VERSION 5.8 ;
BUSBITCHARS "[]" ;
DIVIDERCHAR "/" ;
UNITS
    DATABASE MICRONS 1000 ;
END UNITS

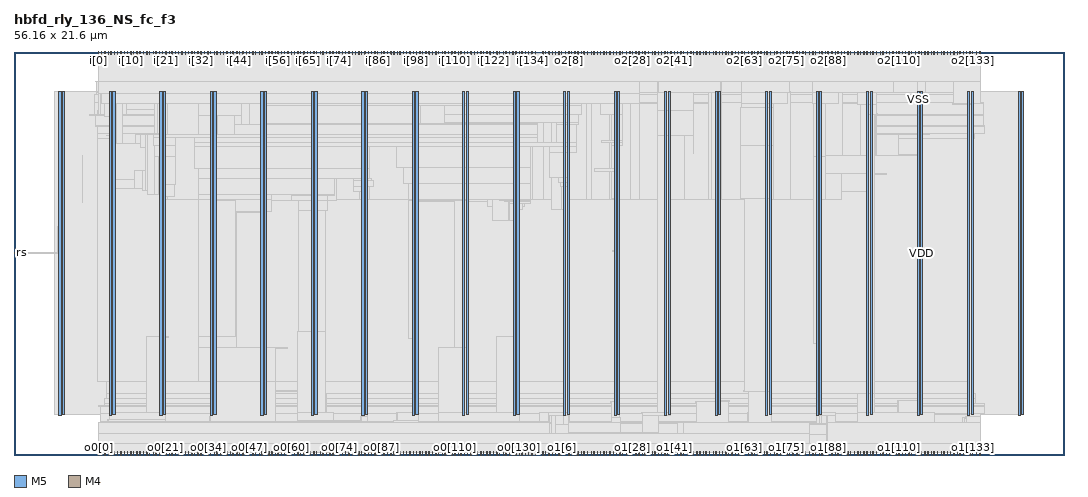
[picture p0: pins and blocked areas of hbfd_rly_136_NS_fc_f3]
MACRO hbfd_rly_136_NS_fc_f3
  FOREIGN hbfd_rly_136_NS_fc_f3 0 0 ;
  CLASS BLOCK ;
  SIZE 56.16 BY 21.6 ;
  PIN clk_in
    DIRECTION INPUT ;
    USE SIGNAL ;
    PORT
      LAYER M5 ;
        RECT  16.176 21.408 16.2 21.6 ;
    END
  END clk_in
  PIN clk_out0
    DIRECTION OUTPUT ;
    USE SIGNAL ;
    PORT
      LAYER M5 ;
        RECT  16.176 0 16.2 0.192 ;
    END
  END clk_out0
  PIN clk_out1
    DIRECTION OUTPUT ;
    USE SIGNAL ;
    PORT
      LAYER M5 ;
        RECT  39.936 0 39.96 0.192 ;
    END
  END clk_out1
  PIN clk_out2
    DIRECTION OUTPUT ;
    USE SIGNAL ;
    PORT
      LAYER M5 ;
        RECT  39.936 21.408 39.96 21.6 ;
    END
  END clk_out2
  PIN i[0]
    DIRECTION INPUT ;
    USE SIGNAL ;
    PORT
      LAYER M5 ;
        RECT  4.512 21.408 4.536 21.6 ;
    END
  END i[0]
  PIN i[100]
    DIRECTION INPUT ;
    USE SIGNAL ;
    PORT
      LAYER M5 ;
        RECT  21.84 21.408 21.864 21.6 ;
    END
  END i[100]
  PIN i[101]
    DIRECTION INPUT ;
    USE SIGNAL ;
    PORT
      LAYER M5 ;
        RECT  22.032 21.408 22.056 21.6 ;
    END
  END i[101]
  PIN i[102]
    DIRECTION INPUT ;
    USE SIGNAL ;
    PORT
      LAYER M5 ;
        RECT  22.176 21.408 22.2 21.6 ;
    END
  END i[102]
  PIN i[103]
    DIRECTION INPUT ;
    USE SIGNAL ;
    PORT
      LAYER M5 ;
        RECT  22.368 21.408 22.392 21.6 ;
    END
  END i[103]
  PIN i[104]
    DIRECTION INPUT ;
    USE SIGNAL ;
    PORT
      LAYER M5 ;
        RECT  22.56 21.408 22.584 21.6 ;
    END
  END i[104]
  PIN i[105]
    DIRECTION INPUT ;
    USE SIGNAL ;
    PORT
      LAYER M5 ;
        RECT  22.704 21.408 22.728 21.6 ;
    END
  END i[105]
  PIN i[106]
    DIRECTION INPUT ;
    USE SIGNAL ;
    PORT
      LAYER M5 ;
        RECT  22.896 21.408 22.92 21.6 ;
    END
  END i[106]
  PIN i[107]
    DIRECTION INPUT ;
    USE SIGNAL ;
    PORT
      LAYER M5 ;
        RECT  23.04 21.408 23.064 21.6 ;
    END
  END i[107]
  PIN i[108]
    DIRECTION INPUT ;
    USE SIGNAL ;
    PORT
      LAYER M5 ;
        RECT  23.232 21.408 23.256 21.6 ;
    END
  END i[108]
  PIN i[109]
    DIRECTION INPUT ;
    USE SIGNAL ;
    PORT
      LAYER M5 ;
        RECT  23.424 21.408 23.448 21.6 ;
    END
  END i[109]
  PIN i[10]
    DIRECTION INPUT ;
    USE SIGNAL ;
    PORT
      LAYER M5 ;
        RECT  6.24 21.408 6.264 21.6 ;
    END
  END i[10]
  PIN i[110]
    DIRECTION INPUT ;
    USE SIGNAL ;
    PORT
      LAYER M5 ;
        RECT  23.568 21.408 23.592 21.6 ;
    END
  END i[110]
  PIN i[111]
    DIRECTION INPUT ;
    USE SIGNAL ;
    PORT
      LAYER M5 ;
        RECT  23.76 21.408 23.784 21.6 ;
    END
  END i[111]
  PIN i[112]
    DIRECTION INPUT ;
    USE SIGNAL ;
    PORT
      LAYER M5 ;
        RECT  23.904 21.408 23.928 21.6 ;
    END
  END i[112]
  PIN i[113]
    DIRECTION INPUT ;
    USE SIGNAL ;
    PORT
      LAYER M5 ;
        RECT  24.096 21.408 24.12 21.6 ;
    END
  END i[113]
  PIN i[114]
    DIRECTION INPUT ;
    USE SIGNAL ;
    PORT
      LAYER M5 ;
        RECT  24.24 21.408 24.264 21.6 ;
    END
  END i[114]
  PIN i[115]
    DIRECTION INPUT ;
    USE SIGNAL ;
    PORT
      LAYER M5 ;
        RECT  24.432 21.408 24.456 21.6 ;
    END
  END i[115]
  PIN i[116]
    DIRECTION INPUT ;
    USE SIGNAL ;
    PORT
      LAYER M5 ;
        RECT  24.624 21.408 24.648 21.6 ;
    END
  END i[116]
  PIN i[117]
    DIRECTION INPUT ;
    USE SIGNAL ;
    PORT
      LAYER M5 ;
        RECT  24.768 21.408 24.792 21.6 ;
    END
  END i[117]
  PIN i[118]
    DIRECTION INPUT ;
    USE SIGNAL ;
    PORT
      LAYER M5 ;
        RECT  24.96 21.408 24.984 21.6 ;
    END
  END i[118]
  PIN i[119]
    DIRECTION INPUT ;
    USE SIGNAL ;
    PORT
      LAYER M5 ;
        RECT  25.104 21.408 25.128 21.6 ;
    END
  END i[119]
  PIN i[11]
    DIRECTION INPUT ;
    USE SIGNAL ;
    PORT
      LAYER M5 ;
        RECT  6.384 21.408 6.408 21.6 ;
    END
  END i[11]
  PIN i[120]
    DIRECTION INPUT ;
    USE SIGNAL ;
    PORT
      LAYER M5 ;
        RECT  25.296 21.408 25.32 21.6 ;
    END
  END i[120]
  PIN i[121]
    DIRECTION INPUT ;
    USE SIGNAL ;
    PORT
      LAYER M5 ;
        RECT  25.44 21.408 25.464 21.6 ;
    END
  END i[121]
  PIN i[122]
    DIRECTION INPUT ;
    USE SIGNAL ;
    PORT
      LAYER M5 ;
        RECT  25.632 21.408 25.656 21.6 ;
    END
  END i[122]
  PIN i[123]
    DIRECTION INPUT ;
    USE SIGNAL ;
    PORT
      LAYER M5 ;
        RECT  25.824 21.408 25.848 21.6 ;
    END
  END i[123]
  PIN i[124]
    DIRECTION INPUT ;
    USE SIGNAL ;
    PORT
      LAYER M5 ;
        RECT  25.968 21.408 25.992 21.6 ;
    END
  END i[124]
  PIN i[125]
    DIRECTION INPUT ;
    USE SIGNAL ;
    PORT
      LAYER M5 ;
        RECT  26.16 21.408 26.184 21.6 ;
    END
  END i[125]
  PIN i[126]
    DIRECTION INPUT ;
    USE SIGNAL ;
    PORT
      LAYER M5 ;
        RECT  26.304 21.408 26.328 21.6 ;
    END
  END i[126]
  PIN i[127]
    DIRECTION INPUT ;
    USE SIGNAL ;
    PORT
      LAYER M5 ;
        RECT  26.496 21.408 26.52 21.6 ;
    END
  END i[127]
  PIN i[128]
    DIRECTION INPUT ;
    USE SIGNAL ;
    PORT
      LAYER M5 ;
        RECT  26.688 21.408 26.712 21.6 ;
    END
  END i[128]
  PIN i[129]
    DIRECTION INPUT ;
    USE SIGNAL ;
    PORT
      LAYER M5 ;
        RECT  26.832 21.408 26.856 21.6 ;
    END
  END i[129]
  PIN i[12]
    DIRECTION INPUT ;
    USE SIGNAL ;
    PORT
      LAYER M5 ;
        RECT  6.576 21.408 6.6 21.6 ;
    END
  END i[12]
  PIN i[130]
    DIRECTION INPUT ;
    USE SIGNAL ;
    PORT
      LAYER M5 ;
        RECT  27.024 21.408 27.048 21.6 ;
    END
  END i[130]
  PIN i[131]
    DIRECTION INPUT ;
    USE SIGNAL ;
    PORT
      LAYER M5 ;
        RECT  27.168 21.408 27.192 21.6 ;
    END
  END i[131]
  PIN i[132]
    DIRECTION INPUT ;
    USE SIGNAL ;
    PORT
      LAYER M5 ;
        RECT  27.36 21.408 27.384 21.6 ;
    END
  END i[132]
  PIN i[133]
    DIRECTION INPUT ;
    USE SIGNAL ;
    PORT
      LAYER M5 ;
        RECT  27.504 21.408 27.528 21.6 ;
    END
  END i[133]
  PIN i[134]
    DIRECTION INPUT ;
    USE SIGNAL ;
    PORT
      LAYER M5 ;
        RECT  27.696 21.408 27.72 21.6 ;
    END
  END i[134]
  PIN i[135]
    DIRECTION INPUT ;
    USE SIGNAL ;
    PORT
      LAYER M5 ;
        RECT  27.888 21.408 27.912 21.6 ;
    END
  END i[135]
  PIN i[13]
    DIRECTION INPUT ;
    USE SIGNAL ;
    PORT
      LAYER M5 ;
        RECT  6.72 21.408 6.744 21.6 ;
    END
  END i[13]
  PIN i[14]
    DIRECTION INPUT ;
    USE SIGNAL ;
    PORT
      LAYER M5 ;
        RECT  6.912 21.408 6.936 21.6 ;
    END
  END i[14]
  PIN i[15]
    DIRECTION INPUT ;
    USE SIGNAL ;
    PORT
      LAYER M5 ;
        RECT  7.104 21.408 7.128 21.6 ;
    END
  END i[15]
  PIN i[16]
    DIRECTION INPUT ;
    USE SIGNAL ;
    PORT
      LAYER M5 ;
        RECT  7.248 21.408 7.272 21.6 ;
    END
  END i[16]
  PIN i[17]
    DIRECTION INPUT ;
    USE SIGNAL ;
    PORT
      LAYER M5 ;
        RECT  7.44 21.408 7.464 21.6 ;
    END
  END i[17]
  PIN i[18]
    DIRECTION INPUT ;
    USE SIGNAL ;
    PORT
      LAYER M5 ;
        RECT  7.584 21.408 7.608 21.6 ;
    END
  END i[18]
  PIN i[19]
    DIRECTION INPUT ;
    USE SIGNAL ;
    PORT
      LAYER M5 ;
        RECT  7.776 21.408 7.8 21.6 ;
    END
  END i[19]
  PIN i[1]
    DIRECTION INPUT ;
    USE SIGNAL ;
    PORT
      LAYER M5 ;
        RECT  4.656 21.408 4.68 21.6 ;
    END
  END i[1]
  PIN i[20]
    DIRECTION INPUT ;
    USE SIGNAL ;
    PORT
      LAYER M5 ;
        RECT  7.92 21.408 7.944 21.6 ;
    END
  END i[20]
  PIN i[21]
    DIRECTION INPUT ;
    USE SIGNAL ;
    PORT
      LAYER M5 ;
        RECT  8.112 21.408 8.136 21.6 ;
    END
  END i[21]
  PIN i[22]
    DIRECTION INPUT ;
    USE SIGNAL ;
    PORT
      LAYER M5 ;
        RECT  8.304 21.408 8.328 21.6 ;
    END
  END i[22]
  PIN i[23]
    DIRECTION INPUT ;
    USE SIGNAL ;
    PORT
      LAYER M5 ;
        RECT  8.448 21.408 8.472 21.6 ;
    END
  END i[23]
  PIN i[24]
    DIRECTION INPUT ;
    USE SIGNAL ;
    PORT
      LAYER M5 ;
        RECT  8.64 21.408 8.664 21.6 ;
    END
  END i[24]
  PIN i[25]
    DIRECTION INPUT ;
    USE SIGNAL ;
    PORT
      LAYER M5 ;
        RECT  8.784 21.408 8.808 21.6 ;
    END
  END i[25]
  PIN i[26]
    DIRECTION INPUT ;
    USE SIGNAL ;
    PORT
      LAYER M5 ;
        RECT  8.976 21.408 9 21.6 ;
    END
  END i[26]
  PIN i[27]
    DIRECTION INPUT ;
    USE SIGNAL ;
    PORT
      LAYER M5 ;
        RECT  9.168 21.408 9.192 21.6 ;
    END
  END i[27]
  PIN i[28]
    DIRECTION INPUT ;
    USE SIGNAL ;
    PORT
      LAYER M5 ;
        RECT  9.312 21.408 9.336 21.6 ;
    END
  END i[28]
  PIN i[29]
    DIRECTION INPUT ;
    USE SIGNAL ;
    PORT
      LAYER M5 ;
        RECT  9.504 21.408 9.528 21.6 ;
    END
  END i[29]
  PIN i[2]
    DIRECTION INPUT ;
    USE SIGNAL ;
    PORT
      LAYER M5 ;
        RECT  4.848 21.408 4.872 21.6 ;
    END
  END i[2]
  PIN i[30]
    DIRECTION INPUT ;
    USE SIGNAL ;
    PORT
      LAYER M5 ;
        RECT  9.648 21.408 9.672 21.6 ;
    END
  END i[30]
  PIN i[31]
    DIRECTION INPUT ;
    USE SIGNAL ;
    PORT
      LAYER M5 ;
        RECT  9.84 21.408 9.864 21.6 ;
    END
  END i[31]
  PIN i[32]
    DIRECTION INPUT ;
    USE SIGNAL ;
    PORT
      LAYER M5 ;
        RECT  9.984 21.408 10.008 21.6 ;
    END
  END i[32]
  PIN i[33]
    DIRECTION INPUT ;
    USE SIGNAL ;
    PORT
      LAYER M5 ;
        RECT  10.176 21.408 10.2 21.6 ;
    END
  END i[33]
  PIN i[34]
    DIRECTION INPUT ;
    USE SIGNAL ;
    PORT
      LAYER M5 ;
        RECT  10.368 21.408 10.392 21.6 ;
    END
  END i[34]
  PIN i[35]
    DIRECTION INPUT ;
    USE SIGNAL ;
    PORT
      LAYER M5 ;
        RECT  10.512 21.408 10.536 21.6 ;
    END
  END i[35]
  PIN i[36]
    DIRECTION INPUT ;
    USE SIGNAL ;
    PORT
      LAYER M5 ;
        RECT  10.704 21.408 10.728 21.6 ;
    END
  END i[36]
  PIN i[37]
    DIRECTION INPUT ;
    USE SIGNAL ;
    PORT
      LAYER M5 ;
        RECT  10.848 21.408 10.872 21.6 ;
    END
  END i[37]
  PIN i[38]
    DIRECTION INPUT ;
    USE SIGNAL ;
    PORT
      LAYER M5 ;
        RECT  11.04 21.408 11.064 21.6 ;
    END
  END i[38]
  PIN i[39]
    DIRECTION INPUT ;
    USE SIGNAL ;
    PORT
      LAYER M5 ;
        RECT  11.184 21.408 11.208 21.6 ;
    END
  END i[39]
  PIN i[3]
    DIRECTION INPUT ;
    USE SIGNAL ;
    PORT
      LAYER M5 ;
        RECT  5.04 21.408 5.064 21.6 ;
    END
  END i[3]
  PIN i[40]
    DIRECTION INPUT ;
    USE SIGNAL ;
    PORT
      LAYER M5 ;
        RECT  11.376 21.408 11.4 21.6 ;
    END
  END i[40]
  PIN i[41]
    DIRECTION INPUT ;
    USE SIGNAL ;
    PORT
      LAYER M5 ;
        RECT  11.568 21.408 11.592 21.6 ;
    END
  END i[41]
  PIN i[42]
    DIRECTION INPUT ;
    USE SIGNAL ;
    PORT
      LAYER M5 ;
        RECT  11.712 21.408 11.736 21.6 ;
    END
  END i[42]
  PIN i[43]
    DIRECTION INPUT ;
    USE SIGNAL ;
    PORT
      LAYER M5 ;
        RECT  11.904 21.408 11.928 21.6 ;
    END
  END i[43]
  PIN i[44]
    DIRECTION INPUT ;
    USE SIGNAL ;
    PORT
      LAYER M5 ;
        RECT  12.048 21.408 12.072 21.6 ;
    END
  END i[44]
  PIN i[45]
    DIRECTION INPUT ;
    USE SIGNAL ;
    PORT
      LAYER M5 ;
        RECT  12.24 21.408 12.264 21.6 ;
    END
  END i[45]
  PIN i[46]
    DIRECTION INPUT ;
    USE SIGNAL ;
    PORT
      LAYER M5 ;
        RECT  12.432 21.408 12.456 21.6 ;
    END
  END i[46]
  PIN i[47]
    DIRECTION INPUT ;
    USE SIGNAL ;
    PORT
      LAYER M5 ;
        RECT  12.576 21.408 12.6 21.6 ;
    END
  END i[47]
  PIN i[48]
    DIRECTION INPUT ;
    USE SIGNAL ;
    PORT
      LAYER M5 ;
        RECT  12.768 21.408 12.792 21.6 ;
    END
  END i[48]
  PIN i[49]
    DIRECTION INPUT ;
    USE SIGNAL ;
    PORT
      LAYER M5 ;
        RECT  12.912 21.408 12.936 21.6 ;
    END
  END i[49]
  PIN i[4]
    DIRECTION INPUT ;
    USE SIGNAL ;
    PORT
      LAYER M5 ;
        RECT  5.184 21.408 5.208 21.6 ;
    END
  END i[4]
  PIN i[50]
    DIRECTION INPUT ;
    USE SIGNAL ;
    PORT
      LAYER M5 ;
        RECT  13.104 21.408 13.128 21.6 ;
    END
  END i[50]
  PIN i[51]
    DIRECTION INPUT ;
    USE SIGNAL ;
    PORT
      LAYER M5 ;
        RECT  13.248 21.408 13.272 21.6 ;
    END
  END i[51]
  PIN i[52]
    DIRECTION INPUT ;
    USE SIGNAL ;
    PORT
      LAYER M5 ;
        RECT  13.44 21.408 13.464 21.6 ;
    END
  END i[52]
  PIN i[53]
    DIRECTION INPUT ;
    USE SIGNAL ;
    PORT
      LAYER M5 ;
        RECT  13.632 21.408 13.656 21.6 ;
    END
  END i[53]
  PIN i[54]
    DIRECTION INPUT ;
    USE SIGNAL ;
    PORT
      LAYER M5 ;
        RECT  13.776 21.408 13.8 21.6 ;
    END
  END i[54]
  PIN i[55]
    DIRECTION INPUT ;
    USE SIGNAL ;
    PORT
      LAYER M5 ;
        RECT  13.968 21.408 13.992 21.6 ;
    END
  END i[55]
  PIN i[56]
    DIRECTION INPUT ;
    USE SIGNAL ;
    PORT
      LAYER M5 ;
        RECT  14.112 21.408 14.136 21.6 ;
    END
  END i[56]
  PIN i[57]
    DIRECTION INPUT ;
    USE SIGNAL ;
    PORT
      LAYER M5 ;
        RECT  14.304 21.408 14.328 21.6 ;
    END
  END i[57]
  PIN i[58]
    DIRECTION INPUT ;
    USE SIGNAL ;
    PORT
      LAYER M5 ;
        RECT  14.448 21.408 14.472 21.6 ;
    END
  END i[58]
  PIN i[59]
    DIRECTION INPUT ;
    USE SIGNAL ;
    PORT
      LAYER M5 ;
        RECT  14.64 21.408 14.664 21.6 ;
    END
  END i[59]
  PIN i[5]
    DIRECTION INPUT ;
    USE SIGNAL ;
    PORT
      LAYER M5 ;
        RECT  5.376 21.408 5.4 21.6 ;
    END
  END i[5]
  PIN i[60]
    DIRECTION INPUT ;
    USE SIGNAL ;
    PORT
      LAYER M5 ;
        RECT  14.832 21.408 14.856 21.6 ;
    END
  END i[60]
  PIN i[61]
    DIRECTION INPUT ;
    USE SIGNAL ;
    PORT
      LAYER M5 ;
        RECT  14.976 21.408 15 21.6 ;
    END
  END i[61]
  PIN i[62]
    DIRECTION INPUT ;
    USE SIGNAL ;
    PORT
      LAYER M5 ;
        RECT  15.168 21.408 15.192 21.6 ;
    END
  END i[62]
  PIN i[63]
    DIRECTION INPUT ;
    USE SIGNAL ;
    PORT
      LAYER M5 ;
        RECT  15.312 21.408 15.336 21.6 ;
    END
  END i[63]
  PIN i[64]
    DIRECTION INPUT ;
    USE SIGNAL ;
    PORT
      LAYER M5 ;
        RECT  15.504 21.408 15.528 21.6 ;
    END
  END i[64]
  PIN i[65]
    DIRECTION INPUT ;
    USE SIGNAL ;
    PORT
      LAYER M5 ;
        RECT  15.696 21.408 15.72 21.6 ;
    END
  END i[65]
  PIN i[66]
    DIRECTION INPUT ;
    USE SIGNAL ;
    PORT
      LAYER M5 ;
        RECT  15.84 21.408 15.864 21.6 ;
    END
  END i[66]
  PIN i[67]
    DIRECTION INPUT ;
    USE SIGNAL ;
    PORT
      LAYER M5 ;
        RECT  16.032 21.408 16.056 21.6 ;
    END
  END i[67]
  PIN i[68]
    DIRECTION INPUT ;
    USE SIGNAL ;
    PORT
      LAYER M5 ;
        RECT  16.368 21.408 16.392 21.6 ;
    END
  END i[68]
  PIN i[69]
    DIRECTION INPUT ;
    USE SIGNAL ;
    PORT
      LAYER M5 ;
        RECT  16.512 21.408 16.536 21.6 ;
    END
  END i[69]
  PIN i[6]
    DIRECTION INPUT ;
    USE SIGNAL ;
    PORT
      LAYER M5 ;
        RECT  5.52 21.408 5.544 21.6 ;
    END
  END i[6]
  PIN i[70]
    DIRECTION INPUT ;
    USE SIGNAL ;
    PORT
      LAYER M5 ;
        RECT  16.704 21.408 16.728 21.6 ;
    END
  END i[70]
  PIN i[71]
    DIRECTION INPUT ;
    USE SIGNAL ;
    PORT
      LAYER M5 ;
        RECT  16.896 21.408 16.92 21.6 ;
    END
  END i[71]
  PIN i[72]
    DIRECTION INPUT ;
    USE SIGNAL ;
    PORT
      LAYER M5 ;
        RECT  17.04 21.408 17.064 21.6 ;
    END
  END i[72]
  PIN i[73]
    DIRECTION INPUT ;
    USE SIGNAL ;
    PORT
      LAYER M5 ;
        RECT  17.232 21.408 17.256 21.6 ;
    END
  END i[73]
  PIN i[74]
    DIRECTION INPUT ;
    USE SIGNAL ;
    PORT
      LAYER M5 ;
        RECT  17.376 21.408 17.4 21.6 ;
    END
  END i[74]
  PIN i[75]
    DIRECTION INPUT ;
    USE SIGNAL ;
    PORT
      LAYER M5 ;
        RECT  17.568 21.408 17.592 21.6 ;
    END
  END i[75]
  PIN i[76]
    DIRECTION INPUT ;
    USE SIGNAL ;
    PORT
      LAYER M5 ;
        RECT  17.712 21.408 17.736 21.6 ;
    END
  END i[76]
  PIN i[77]
    DIRECTION INPUT ;
    USE SIGNAL ;
    PORT
      LAYER M5 ;
        RECT  17.904 21.408 17.928 21.6 ;
    END
  END i[77]
  PIN i[78]
    DIRECTION INPUT ;
    USE SIGNAL ;
    PORT
      LAYER M5 ;
        RECT  18.096 21.408 18.12 21.6 ;
    END
  END i[78]
  PIN i[79]
    DIRECTION INPUT ;
    USE SIGNAL ;
    PORT
      LAYER M5 ;
        RECT  18.24 21.408 18.264 21.6 ;
    END
  END i[79]
  PIN i[7]
    DIRECTION INPUT ;
    USE SIGNAL ;
    PORT
      LAYER M5 ;
        RECT  5.712 21.408 5.736 21.6 ;
    END
  END i[7]
  PIN i[80]
    DIRECTION INPUT ;
    USE SIGNAL ;
    PORT
      LAYER M5 ;
        RECT  18.432 21.408 18.456 21.6 ;
    END
  END i[80]
  PIN i[81]
    DIRECTION INPUT ;
    USE SIGNAL ;
    PORT
      LAYER M5 ;
        RECT  18.576 21.408 18.6 21.6 ;
    END
  END i[81]
  PIN i[82]
    DIRECTION INPUT ;
    USE SIGNAL ;
    PORT
      LAYER M5 ;
        RECT  18.768 21.408 18.792 21.6 ;
    END
  END i[82]
  PIN i[83]
    DIRECTION INPUT ;
    USE SIGNAL ;
    PORT
      LAYER M5 ;
        RECT  18.96 21.408 18.984 21.6 ;
    END
  END i[83]
  PIN i[84]
    DIRECTION INPUT ;
    USE SIGNAL ;
    PORT
      LAYER M5 ;
        RECT  19.104 21.408 19.128 21.6 ;
    END
  END i[84]
  PIN i[85]
    DIRECTION INPUT ;
    USE SIGNAL ;
    PORT
      LAYER M5 ;
        RECT  19.296 21.408 19.32 21.6 ;
    END
  END i[85]
  PIN i[86]
    DIRECTION INPUT ;
    USE SIGNAL ;
    PORT
      LAYER M5 ;
        RECT  19.44 21.408 19.464 21.6 ;
    END
  END i[86]
  PIN i[87]
    DIRECTION INPUT ;
    USE SIGNAL ;
    PORT
      LAYER M5 ;
        RECT  19.632 21.408 19.656 21.6 ;
    END
  END i[87]
  PIN i[88]
    DIRECTION INPUT ;
    USE SIGNAL ;
    PORT
      LAYER M5 ;
        RECT  19.776 21.408 19.8 21.6 ;
    END
  END i[88]
  PIN i[89]
    DIRECTION INPUT ;
    USE SIGNAL ;
    PORT
      LAYER M5 ;
        RECT  19.968 21.408 19.992 21.6 ;
    END
  END i[89]
  PIN i[8]
    DIRECTION INPUT ;
    USE SIGNAL ;
    PORT
      LAYER M5 ;
        RECT  5.904 21.408 5.928 21.6 ;
    END
  END i[8]
  PIN i[90]
    DIRECTION INPUT ;
    USE SIGNAL ;
    PORT
      LAYER M5 ;
        RECT  20.16 21.408 20.184 21.6 ;
    END
  END i[90]
  PIN i[91]
    DIRECTION INPUT ;
    USE SIGNAL ;
    PORT
      LAYER M5 ;
        RECT  20.304 21.408 20.328 21.6 ;
    END
  END i[91]
  PIN i[92]
    DIRECTION INPUT ;
    USE SIGNAL ;
    PORT
      LAYER M5 ;
        RECT  20.496 21.408 20.52 21.6 ;
    END
  END i[92]
  PIN i[93]
    DIRECTION INPUT ;
    USE SIGNAL ;
    PORT
      LAYER M5 ;
        RECT  20.64 21.408 20.664 21.6 ;
    END
  END i[93]
  PIN i[94]
    DIRECTION INPUT ;
    USE SIGNAL ;
    PORT
      LAYER M5 ;
        RECT  20.832 21.408 20.856 21.6 ;
    END
  END i[94]
  PIN i[95]
    DIRECTION INPUT ;
    USE SIGNAL ;
    PORT
      LAYER M5 ;
        RECT  20.976 21.408 21 21.6 ;
    END
  END i[95]
  PIN i[96]
    DIRECTION INPUT ;
    USE SIGNAL ;
    PORT
      LAYER M5 ;
        RECT  21.168 21.408 21.192 21.6 ;
    END
  END i[96]
  PIN i[97]
    DIRECTION INPUT ;
    USE SIGNAL ;
    PORT
      LAYER M5 ;
        RECT  21.36 21.408 21.384 21.6 ;
    END
  END i[97]
  PIN i[98]
    DIRECTION INPUT ;
    USE SIGNAL ;
    PORT
      LAYER M5 ;
        RECT  21.504 21.408 21.528 21.6 ;
    END
  END i[98]
  PIN i[99]
    DIRECTION INPUT ;
    USE SIGNAL ;
    PORT
      LAYER M5 ;
        RECT  21.696 21.408 21.72 21.6 ;
    END
  END i[99]
  PIN i[9]
    DIRECTION INPUT ;
    USE SIGNAL ;
    PORT
      LAYER M5 ;
        RECT  6.048 21.408 6.072 21.6 ;
    END
  END i[9]
  PIN o0[0]
    DIRECTION OUTPUT ;
    USE SIGNAL ;
    PORT
      LAYER M5 ;
        RECT  4.512 0 4.536 0.192 ;
    END
  END o0[0]
  PIN o0[100]
    DIRECTION OUTPUT ;
    USE SIGNAL ;
    PORT
      LAYER M5 ;
        RECT  21.84 0 21.864 0.192 ;
    END
  END o0[100]
  PIN o0[101]
    DIRECTION OUTPUT ;
    USE SIGNAL ;
    PORT
      LAYER M5 ;
        RECT  22.032 0 22.056 0.192 ;
    END
  END o0[101]
  PIN o0[102]
    DIRECTION OUTPUT ;
    USE SIGNAL ;
    PORT
      LAYER M5 ;
        RECT  22.176 0 22.2 0.192 ;
    END
  END o0[102]
  PIN o0[103]
    DIRECTION OUTPUT ;
    USE SIGNAL ;
    PORT
      LAYER M5 ;
        RECT  22.368 0 22.392 0.192 ;
    END
  END o0[103]
  PIN o0[104]
    DIRECTION OUTPUT ;
    USE SIGNAL ;
    PORT
      LAYER M5 ;
        RECT  22.56 0 22.584 0.192 ;
    END
  END o0[104]
  PIN o0[105]
    DIRECTION OUTPUT ;
    USE SIGNAL ;
    PORT
      LAYER M5 ;
        RECT  22.704 0 22.728 0.192 ;
    END
  END o0[105]
  PIN o0[106]
    DIRECTION OUTPUT ;
    USE SIGNAL ;
    PORT
      LAYER M5 ;
        RECT  22.896 0 22.92 0.192 ;
    END
  END o0[106]
  PIN o0[107]
    DIRECTION OUTPUT ;
    USE SIGNAL ;
    PORT
      LAYER M5 ;
        RECT  23.04 0 23.064 0.192 ;
    END
  END o0[107]
  PIN o0[108]
    DIRECTION OUTPUT ;
    USE SIGNAL ;
    PORT
      LAYER M5 ;
        RECT  23.232 0 23.256 0.192 ;
    END
  END o0[108]
  PIN o0[109]
    DIRECTION OUTPUT ;
    USE SIGNAL ;
    PORT
      LAYER M5 ;
        RECT  23.424 0 23.448 0.192 ;
    END
  END o0[109]
  PIN o0[10]
    DIRECTION OUTPUT ;
    USE SIGNAL ;
    PORT
      LAYER M5 ;
        RECT  6.24 0 6.264 0.192 ;
    END
  END o0[10]
  PIN o0[110]
    DIRECTION OUTPUT ;
    USE SIGNAL ;
    PORT
      LAYER M5 ;
        RECT  23.568 0 23.592 0.192 ;
    END
  END o0[110]
  PIN o0[111]
    DIRECTION OUTPUT ;
    USE SIGNAL ;
    PORT
      LAYER M5 ;
        RECT  23.76 0 23.784 0.192 ;
    END
  END o0[111]
  PIN o0[112]
    DIRECTION OUTPUT ;
    USE SIGNAL ;
    PORT
      LAYER M5 ;
        RECT  23.904 0 23.928 0.192 ;
    END
  END o0[112]
  PIN o0[113]
    DIRECTION OUTPUT ;
    USE SIGNAL ;
    PORT
      LAYER M5 ;
        RECT  24.096 0 24.12 0.192 ;
    END
  END o0[113]
  PIN o0[114]
    DIRECTION OUTPUT ;
    USE SIGNAL ;
    PORT
      LAYER M5 ;
        RECT  24.24 0 24.264 0.192 ;
    END
  END o0[114]
  PIN o0[115]
    DIRECTION OUTPUT ;
    USE SIGNAL ;
    PORT
      LAYER M5 ;
        RECT  24.432 0 24.456 0.192 ;
    END
  END o0[115]
  PIN o0[116]
    DIRECTION OUTPUT ;
    USE SIGNAL ;
    PORT
      LAYER M5 ;
        RECT  24.624 0 24.648 0.192 ;
    END
  END o0[116]
  PIN o0[117]
    DIRECTION OUTPUT ;
    USE SIGNAL ;
    PORT
      LAYER M5 ;
        RECT  24.768 0 24.792 0.192 ;
    END
  END o0[117]
  PIN o0[118]
    DIRECTION OUTPUT ;
    USE SIGNAL ;
    PORT
      LAYER M5 ;
        RECT  24.96 0 24.984 0.192 ;
    END
  END o0[118]
  PIN o0[119]
    DIRECTION OUTPUT ;
    USE SIGNAL ;
    PORT
      LAYER M5 ;
        RECT  25.104 0 25.128 0.192 ;
    END
  END o0[119]
  PIN o0[11]
    DIRECTION OUTPUT ;
    USE SIGNAL ;
    PORT
      LAYER M5 ;
        RECT  6.384 0 6.408 0.192 ;
    END
  END o0[11]
  PIN o0[120]
    DIRECTION OUTPUT ;
    USE SIGNAL ;
    PORT
      LAYER M5 ;
        RECT  25.296 0 25.32 0.192 ;
    END
  END o0[120]
  PIN o0[121]
    DIRECTION OUTPUT ;
    USE SIGNAL ;
    PORT
      LAYER M5 ;
        RECT  25.44 0 25.464 0.192 ;
    END
  END o0[121]
  PIN o0[122]
    DIRECTION OUTPUT ;
    USE SIGNAL ;
    PORT
      LAYER M5 ;
        RECT  25.632 0 25.656 0.192 ;
    END
  END o0[122]
  PIN o0[123]
    DIRECTION OUTPUT ;
    USE SIGNAL ;
    PORT
      LAYER M5 ;
        RECT  25.824 0 25.848 0.192 ;
    END
  END o0[123]
  PIN o0[124]
    DIRECTION OUTPUT ;
    USE SIGNAL ;
    PORT
      LAYER M5 ;
        RECT  25.968 0 25.992 0.192 ;
    END
  END o0[124]
  PIN o0[125]
    DIRECTION OUTPUT ;
    USE SIGNAL ;
    PORT
      LAYER M5 ;
        RECT  26.16 0 26.184 0.192 ;
    END
  END o0[125]
  PIN o0[126]
    DIRECTION OUTPUT ;
    USE SIGNAL ;
    PORT
      LAYER M5 ;
        RECT  26.304 0 26.328 0.192 ;
    END
  END o0[126]
  PIN o0[127]
    DIRECTION OUTPUT ;
    USE SIGNAL ;
    PORT
      LAYER M5 ;
        RECT  26.496 0 26.52 0.192 ;
    END
  END o0[127]
  PIN o0[128]
    DIRECTION OUTPUT ;
    USE SIGNAL ;
    PORT
      LAYER M5 ;
        RECT  26.688 0 26.712 0.192 ;
    END
  END o0[128]
  PIN o0[129]
    DIRECTION OUTPUT ;
    USE SIGNAL ;
    PORT
      LAYER M5 ;
        RECT  26.832 0 26.856 0.192 ;
    END
  END o0[129]
  PIN o0[12]
    DIRECTION OUTPUT ;
    USE SIGNAL ;
    PORT
      LAYER M5 ;
        RECT  6.576 0 6.6 0.192 ;
    END
  END o0[12]
  PIN o0[130]
    DIRECTION OUTPUT ;
    USE SIGNAL ;
    PORT
      LAYER M5 ;
        RECT  27.024 0 27.048 0.192 ;
    END
  END o0[130]
  PIN o0[131]
    DIRECTION OUTPUT ;
    USE SIGNAL ;
    PORT
      LAYER M5 ;
        RECT  27.168 0 27.192 0.192 ;
    END
  END o0[131]
  PIN o0[132]
    DIRECTION OUTPUT ;
    USE SIGNAL ;
    PORT
      LAYER M5 ;
        RECT  27.36 0 27.384 0.192 ;
    END
  END o0[132]
  PIN o0[133]
    DIRECTION OUTPUT ;
    USE SIGNAL ;
    PORT
      LAYER M5 ;
        RECT  27.504 0 27.528 0.192 ;
    END
  END o0[133]
  PIN o0[134]
    DIRECTION OUTPUT ;
    USE SIGNAL ;
    PORT
      LAYER M5 ;
        RECT  27.696 0 27.72 0.192 ;
    END
  END o0[134]
  PIN o0[135]
    DIRECTION OUTPUT ;
    USE SIGNAL ;
    PORT
      LAYER M5 ;
        RECT  27.888 0 27.912 0.192 ;
    END
  END o0[135]
  PIN o0[13]
    DIRECTION OUTPUT ;
    USE SIGNAL ;
    PORT
      LAYER M5 ;
        RECT  6.72 0 6.744 0.192 ;
    END
  END o0[13]
  PIN o0[14]
    DIRECTION OUTPUT ;
    USE SIGNAL ;
    PORT
      LAYER M5 ;
        RECT  6.912 0 6.936 0.192 ;
    END
  END o0[14]
  PIN o0[15]
    DIRECTION OUTPUT ;
    USE SIGNAL ;
    PORT
      LAYER M5 ;
        RECT  7.104 0 7.128 0.192 ;
    END
  END o0[15]
  PIN o0[16]
    DIRECTION OUTPUT ;
    USE SIGNAL ;
    PORT
      LAYER M5 ;
        RECT  7.248 0 7.272 0.192 ;
    END
  END o0[16]
  PIN o0[17]
    DIRECTION OUTPUT ;
    USE SIGNAL ;
    PORT
      LAYER M5 ;
        RECT  7.44 0 7.464 0.192 ;
    END
  END o0[17]
  PIN o0[18]
    DIRECTION OUTPUT ;
    USE SIGNAL ;
    PORT
      LAYER M5 ;
        RECT  7.584 0 7.608 0.192 ;
    END
  END o0[18]
  PIN o0[19]
    DIRECTION OUTPUT ;
    USE SIGNAL ;
    PORT
      LAYER M5 ;
        RECT  7.776 0 7.8 0.192 ;
    END
  END o0[19]
  PIN o0[1]
    DIRECTION OUTPUT ;
    USE SIGNAL ;
    PORT
      LAYER M5 ;
        RECT  4.656 0 4.68 0.192 ;
    END
  END o0[1]
  PIN o0[20]
    DIRECTION OUTPUT ;
    USE SIGNAL ;
    PORT
      LAYER M5 ;
        RECT  7.92 0 7.944 0.192 ;
    END
  END o0[20]
  PIN o0[21]
    DIRECTION OUTPUT ;
    USE SIGNAL ;
    PORT
      LAYER M5 ;
        RECT  8.112 0 8.136 0.192 ;
    END
  END o0[21]
  PIN o0[22]
    DIRECTION OUTPUT ;
    USE SIGNAL ;
    PORT
      LAYER M5 ;
        RECT  8.304 0 8.328 0.192 ;
    END
  END o0[22]
  PIN o0[23]
    DIRECTION OUTPUT ;
    USE SIGNAL ;
    PORT
      LAYER M5 ;
        RECT  8.448 0 8.472 0.192 ;
    END
  END o0[23]
  PIN o0[24]
    DIRECTION OUTPUT ;
    USE SIGNAL ;
    PORT
      LAYER M5 ;
        RECT  8.64 0 8.664 0.192 ;
    END
  END o0[24]
  PIN o0[25]
    DIRECTION OUTPUT ;
    USE SIGNAL ;
    PORT
      LAYER M5 ;
        RECT  8.784 0 8.808 0.192 ;
    END
  END o0[25]
  PIN o0[26]
    DIRECTION OUTPUT ;
    USE SIGNAL ;
    PORT
      LAYER M5 ;
        RECT  8.976 0 9 0.192 ;
    END
  END o0[26]
  PIN o0[27]
    DIRECTION OUTPUT ;
    USE SIGNAL ;
    PORT
      LAYER M5 ;
        RECT  9.168 0 9.192 0.192 ;
    END
  END o0[27]
  PIN o0[28]
    DIRECTION OUTPUT ;
    USE SIGNAL ;
    PORT
      LAYER M5 ;
        RECT  9.312 0 9.336 0.192 ;
    END
  END o0[28]
  PIN o0[29]
    DIRECTION OUTPUT ;
    USE SIGNAL ;
    PORT
      LAYER M5 ;
        RECT  9.504 0 9.528 0.192 ;
    END
  END o0[29]
  PIN o0[2]
    DIRECTION OUTPUT ;
    USE SIGNAL ;
    PORT
      LAYER M5 ;
        RECT  4.848 0 4.872 0.192 ;
    END
  END o0[2]
  PIN o0[30]
    DIRECTION OUTPUT ;
    USE SIGNAL ;
    PORT
      LAYER M5 ;
        RECT  9.648 0 9.672 0.192 ;
    END
  END o0[30]
  PIN o0[31]
    DIRECTION OUTPUT ;
    USE SIGNAL ;
    PORT
      LAYER M5 ;
        RECT  9.84 0 9.864 0.192 ;
    END
  END o0[31]
  PIN o0[32]
    DIRECTION OUTPUT ;
    USE SIGNAL ;
    PORT
      LAYER M5 ;
        RECT  9.984 0 10.008 0.192 ;
    END
  END o0[32]
  PIN o0[33]
    DIRECTION OUTPUT ;
    USE SIGNAL ;
    PORT
      LAYER M5 ;
        RECT  10.176 0 10.2 0.192 ;
    END
  END o0[33]
  PIN o0[34]
    DIRECTION OUTPUT ;
    USE SIGNAL ;
    PORT
      LAYER M5 ;
        RECT  10.368 0 10.392 0.192 ;
    END
  END o0[34]
  PIN o0[35]
    DIRECTION OUTPUT ;
    USE SIGNAL ;
    PORT
      LAYER M5 ;
        RECT  10.512 0 10.536 0.192 ;
    END
  END o0[35]
  PIN o0[36]
    DIRECTION OUTPUT ;
    USE SIGNAL ;
    PORT
      LAYER M5 ;
        RECT  10.704 0 10.728 0.192 ;
    END
  END o0[36]
  PIN o0[37]
    DIRECTION OUTPUT ;
    USE SIGNAL ;
    PORT
      LAYER M5 ;
        RECT  10.848 0 10.872 0.192 ;
    END
  END o0[37]
  PIN o0[38]
    DIRECTION OUTPUT ;
    USE SIGNAL ;
    PORT
      LAYER M5 ;
        RECT  11.04 0 11.064 0.192 ;
    END
  END o0[38]
  PIN o0[39]
    DIRECTION OUTPUT ;
    USE SIGNAL ;
    PORT
      LAYER M5 ;
        RECT  11.184 0 11.208 0.192 ;
    END
  END o0[39]
  PIN o0[3]
    DIRECTION OUTPUT ;
    USE SIGNAL ;
    PORT
      LAYER M5 ;
        RECT  5.04 0 5.064 0.192 ;
    END
  END o0[3]
  PIN o0[40]
    DIRECTION OUTPUT ;
    USE SIGNAL ;
    PORT
      LAYER M5 ;
        RECT  11.376 0 11.4 0.192 ;
    END
  END o0[40]
  PIN o0[41]
    DIRECTION OUTPUT ;
    USE SIGNAL ;
    PORT
      LAYER M5 ;
        RECT  11.568 0 11.592 0.192 ;
    END
  END o0[41]
  PIN o0[42]
    DIRECTION OUTPUT ;
    USE SIGNAL ;
    PORT
      LAYER M5 ;
        RECT  11.712 0 11.736 0.192 ;
    END
  END o0[42]
  PIN o0[43]
    DIRECTION OUTPUT ;
    USE SIGNAL ;
    PORT
      LAYER M5 ;
        RECT  11.904 0 11.928 0.192 ;
    END
  END o0[43]
  PIN o0[44]
    DIRECTION OUTPUT ;
    USE SIGNAL ;
    PORT
      LAYER M5 ;
        RECT  12.048 0 12.072 0.192 ;
    END
  END o0[44]
  PIN o0[45]
    DIRECTION OUTPUT ;
    USE SIGNAL ;
    PORT
      LAYER M5 ;
        RECT  12.24 0 12.264 0.192 ;
    END
  END o0[45]
  PIN o0[46]
    DIRECTION OUTPUT ;
    USE SIGNAL ;
    PORT
      LAYER M5 ;
        RECT  12.432 0 12.456 0.192 ;
    END
  END o0[46]
  PIN o0[47]
    DIRECTION OUTPUT ;
    USE SIGNAL ;
    PORT
      LAYER M5 ;
        RECT  12.576 0 12.6 0.192 ;
    END
  END o0[47]
  PIN o0[48]
    DIRECTION OUTPUT ;
    USE SIGNAL ;
    PORT
      LAYER M5 ;
        RECT  12.768 0 12.792 0.192 ;
    END
  END o0[48]
  PIN o0[49]
    DIRECTION OUTPUT ;
    USE SIGNAL ;
    PORT
      LAYER M5 ;
        RECT  12.912 0 12.936 0.192 ;
    END
  END o0[49]
  PIN o0[4]
    DIRECTION OUTPUT ;
    USE SIGNAL ;
    PORT
      LAYER M5 ;
        RECT  5.184 0 5.208 0.192 ;
    END
  END o0[4]
  PIN o0[50]
    DIRECTION OUTPUT ;
    USE SIGNAL ;
    PORT
      LAYER M5 ;
        RECT  13.104 0 13.128 0.192 ;
    END
  END o0[50]
  PIN o0[51]
    DIRECTION OUTPUT ;
    USE SIGNAL ;
    PORT
      LAYER M5 ;
        RECT  13.248 0 13.272 0.192 ;
    END
  END o0[51]
  PIN o0[52]
    DIRECTION OUTPUT ;
    USE SIGNAL ;
    PORT
      LAYER M5 ;
        RECT  13.44 0 13.464 0.192 ;
    END
  END o0[52]
  PIN o0[53]
    DIRECTION OUTPUT ;
    USE SIGNAL ;
    PORT
      LAYER M5 ;
        RECT  13.632 0 13.656 0.192 ;
    END
  END o0[53]
  PIN o0[54]
    DIRECTION OUTPUT ;
    USE SIGNAL ;
    PORT
      LAYER M5 ;
        RECT  13.776 0 13.8 0.192 ;
    END
  END o0[54]
  PIN o0[55]
    DIRECTION OUTPUT ;
    USE SIGNAL ;
    PORT
      LAYER M5 ;
        RECT  13.968 0 13.992 0.192 ;
    END
  END o0[55]
  PIN o0[56]
    DIRECTION OUTPUT ;
    USE SIGNAL ;
    PORT
      LAYER M5 ;
        RECT  14.112 0 14.136 0.192 ;
    END
  END o0[56]
  PIN o0[57]
    DIRECTION OUTPUT ;
    USE SIGNAL ;
    PORT
      LAYER M5 ;
        RECT  14.304 0 14.328 0.192 ;
    END
  END o0[57]
  PIN o0[58]
    DIRECTION OUTPUT ;
    USE SIGNAL ;
    PORT
      LAYER M5 ;
        RECT  14.448 0 14.472 0.192 ;
    END
  END o0[58]
  PIN o0[59]
    DIRECTION OUTPUT ;
    USE SIGNAL ;
    PORT
      LAYER M5 ;
        RECT  14.64 0 14.664 0.192 ;
    END
  END o0[59]
  PIN o0[5]
    DIRECTION OUTPUT ;
    USE SIGNAL ;
    PORT
      LAYER M5 ;
        RECT  5.376 0 5.4 0.192 ;
    END
  END o0[5]
  PIN o0[60]
    DIRECTION OUTPUT ;
    USE SIGNAL ;
    PORT
      LAYER M5 ;
        RECT  14.832 0 14.856 0.192 ;
    END
  END o0[60]
  PIN o0[61]
    DIRECTION OUTPUT ;
    USE SIGNAL ;
    PORT
      LAYER M5 ;
        RECT  14.976 0 15 0.192 ;
    END
  END o0[61]
  PIN o0[62]
    DIRECTION OUTPUT ;
    USE SIGNAL ;
    PORT
      LAYER M5 ;
        RECT  15.168 0 15.192 0.192 ;
    END
  END o0[62]
  PIN o0[63]
    DIRECTION OUTPUT ;
    USE SIGNAL ;
    PORT
      LAYER M5 ;
        RECT  15.312 0 15.336 0.192 ;
    END
  END o0[63]
  PIN o0[64]
    DIRECTION OUTPUT ;
    USE SIGNAL ;
    PORT
      LAYER M5 ;
        RECT  15.504 0 15.528 0.192 ;
    END
  END o0[64]
  PIN o0[65]
    DIRECTION OUTPUT ;
    USE SIGNAL ;
    PORT
      LAYER M5 ;
        RECT  15.696 0 15.72 0.192 ;
    END
  END o0[65]
  PIN o0[66]
    DIRECTION OUTPUT ;
    USE SIGNAL ;
    PORT
      LAYER M5 ;
        RECT  15.84 0 15.864 0.192 ;
    END
  END o0[66]
  PIN o0[67]
    DIRECTION OUTPUT ;
    USE SIGNAL ;
    PORT
      LAYER M5 ;
        RECT  16.032 0 16.056 0.192 ;
    END
  END o0[67]
  PIN o0[68]
    DIRECTION OUTPUT ;
    USE SIGNAL ;
    PORT
      LAYER M5 ;
        RECT  16.368 0 16.392 0.192 ;
    END
  END o0[68]
  PIN o0[69]
    DIRECTION OUTPUT ;
    USE SIGNAL ;
    PORT
      LAYER M5 ;
        RECT  16.512 0 16.536 0.192 ;
    END
  END o0[69]
  PIN o0[6]
    DIRECTION OUTPUT ;
    USE SIGNAL ;
    PORT
      LAYER M5 ;
        RECT  5.52 0 5.544 0.192 ;
    END
  END o0[6]
  PIN o0[70]
    DIRECTION OUTPUT ;
    USE SIGNAL ;
    PORT
      LAYER M5 ;
        RECT  16.704 0 16.728 0.192 ;
    END
  END o0[70]
  PIN o0[71]
    DIRECTION OUTPUT ;
    USE SIGNAL ;
    PORT
      LAYER M5 ;
        RECT  16.896 0 16.92 0.192 ;
    END
  END o0[71]
  PIN o0[72]
    DIRECTION OUTPUT ;
    USE SIGNAL ;
    PORT
      LAYER M5 ;
        RECT  17.04 0 17.064 0.192 ;
    END
  END o0[72]
  PIN o0[73]
    DIRECTION OUTPUT ;
    USE SIGNAL ;
    PORT
      LAYER M5 ;
        RECT  17.232 0 17.256 0.192 ;
    END
  END o0[73]
  PIN o0[74]
    DIRECTION OUTPUT ;
    USE SIGNAL ;
    PORT
      LAYER M5 ;
        RECT  17.376 0 17.4 0.192 ;
    END
  END o0[74]
  PIN o0[75]
    DIRECTION OUTPUT ;
    USE SIGNAL ;
    PORT
      LAYER M5 ;
        RECT  17.568 0 17.592 0.192 ;
    END
  END o0[75]
  PIN o0[76]
    DIRECTION OUTPUT ;
    USE SIGNAL ;
    PORT
      LAYER M5 ;
        RECT  17.712 0 17.736 0.192 ;
    END
  END o0[76]
  PIN o0[77]
    DIRECTION OUTPUT ;
    USE SIGNAL ;
    PORT
      LAYER M5 ;
        RECT  17.904 0 17.928 0.192 ;
    END
  END o0[77]
  PIN o0[78]
    DIRECTION OUTPUT ;
    USE SIGNAL ;
    PORT
      LAYER M5 ;
        RECT  18.096 0 18.12 0.192 ;
    END
  END o0[78]
  PIN o0[79]
    DIRECTION OUTPUT ;
    USE SIGNAL ;
    PORT
      LAYER M5 ;
        RECT  18.24 0 18.264 0.192 ;
    END
  END o0[79]
  PIN o0[7]
    DIRECTION OUTPUT ;
    USE SIGNAL ;
    PORT
      LAYER M5 ;
        RECT  5.712 0 5.736 0.192 ;
    END
  END o0[7]
  PIN o0[80]
    DIRECTION OUTPUT ;
    USE SIGNAL ;
    PORT
      LAYER M5 ;
        RECT  18.432 0 18.456 0.192 ;
    END
  END o0[80]
  PIN o0[81]
    DIRECTION OUTPUT ;
    USE SIGNAL ;
    PORT
      LAYER M5 ;
        RECT  18.576 0 18.6 0.192 ;
    END
  END o0[81]
  PIN o0[82]
    DIRECTION OUTPUT ;
    USE SIGNAL ;
    PORT
      LAYER M5 ;
        RECT  18.768 0 18.792 0.192 ;
    END
  END o0[82]
  PIN o0[83]
    DIRECTION OUTPUT ;
    USE SIGNAL ;
    PORT
      LAYER M5 ;
        RECT  18.96 0 18.984 0.192 ;
    END
  END o0[83]
  PIN o0[84]
    DIRECTION OUTPUT ;
    USE SIGNAL ;
    PORT
      LAYER M5 ;
        RECT  19.104 0 19.128 0.192 ;
    END
  END o0[84]
  PIN o0[85]
    DIRECTION OUTPUT ;
    USE SIGNAL ;
    PORT
      LAYER M5 ;
        RECT  19.296 0 19.32 0.192 ;
    END
  END o0[85]
  PIN o0[86]
    DIRECTION OUTPUT ;
    USE SIGNAL ;
    PORT
      LAYER M5 ;
        RECT  19.44 0 19.464 0.192 ;
    END
  END o0[86]
  PIN o0[87]
    DIRECTION OUTPUT ;
    USE SIGNAL ;
    PORT
      LAYER M5 ;
        RECT  19.632 0 19.656 0.192 ;
    END
  END o0[87]
  PIN o0[88]
    DIRECTION OUTPUT ;
    USE SIGNAL ;
    PORT
      LAYER M5 ;
        RECT  19.776 0 19.8 0.192 ;
    END
  END o0[88]
  PIN o0[89]
    DIRECTION OUTPUT ;
    USE SIGNAL ;
    PORT
      LAYER M5 ;
        RECT  19.968 0 19.992 0.192 ;
    END
  END o0[89]
  PIN o0[8]
    DIRECTION OUTPUT ;
    USE SIGNAL ;
    PORT
      LAYER M5 ;
        RECT  5.904 0 5.928 0.192 ;
    END
  END o0[8]
  PIN o0[90]
    DIRECTION OUTPUT ;
    USE SIGNAL ;
    PORT
      LAYER M5 ;
        RECT  20.16 0 20.184 0.192 ;
    END
  END o0[90]
  PIN o0[91]
    DIRECTION OUTPUT ;
    USE SIGNAL ;
    PORT
      LAYER M5 ;
        RECT  20.304 0 20.328 0.192 ;
    END
  END o0[91]
  PIN o0[92]
    DIRECTION OUTPUT ;
    USE SIGNAL ;
    PORT
      LAYER M5 ;
        RECT  20.496 0 20.52 0.192 ;
    END
  END o0[92]
  PIN o0[93]
    DIRECTION OUTPUT ;
    USE SIGNAL ;
    PORT
      LAYER M5 ;
        RECT  20.64 0 20.664 0.192 ;
    END
  END o0[93]
  PIN o0[94]
    DIRECTION OUTPUT ;
    USE SIGNAL ;
    PORT
      LAYER M5 ;
        RECT  20.832 0 20.856 0.192 ;
    END
  END o0[94]
  PIN o0[95]
    DIRECTION OUTPUT ;
    USE SIGNAL ;
    PORT
      LAYER M5 ;
        RECT  20.976 0 21 0.192 ;
    END
  END o0[95]
  PIN o0[96]
    DIRECTION OUTPUT ;
    USE SIGNAL ;
    PORT
      LAYER M5 ;
        RECT  21.168 0 21.192 0.192 ;
    END
  END o0[96]
  PIN o0[97]
    DIRECTION OUTPUT ;
    USE SIGNAL ;
    PORT
      LAYER M5 ;
        RECT  21.36 0 21.384 0.192 ;
    END
  END o0[97]
  PIN o0[98]
    DIRECTION OUTPUT ;
    USE SIGNAL ;
    PORT
      LAYER M5 ;
        RECT  21.504 0 21.528 0.192 ;
    END
  END o0[98]
  PIN o0[99]
    DIRECTION OUTPUT ;
    USE SIGNAL ;
    PORT
      LAYER M5 ;
        RECT  21.696 0 21.72 0.192 ;
    END
  END o0[99]
  PIN o0[9]
    DIRECTION OUTPUT ;
    USE SIGNAL ;
    PORT
      LAYER M5 ;
        RECT  6.048 0 6.072 0.192 ;
    END
  END o0[9]
  PIN o1[0]
    DIRECTION OUTPUT ;
    USE SIGNAL ;
    PORT
      LAYER M5 ;
        RECT  28.272 0 28.296 0.192 ;
    END
  END o1[0]
  PIN o1[100]
    DIRECTION OUTPUT ;
    USE SIGNAL ;
    PORT
      LAYER M5 ;
        RECT  45.6 0 45.624 0.192 ;
    END
  END o1[100]
  PIN o1[101]
    DIRECTION OUTPUT ;
    USE SIGNAL ;
    PORT
      LAYER M5 ;
        RECT  45.792 0 45.816 0.192 ;
    END
  END o1[101]
  PIN o1[102]
    DIRECTION OUTPUT ;
    USE SIGNAL ;
    PORT
      LAYER M5 ;
        RECT  45.936 0 45.96 0.192 ;
    END
  END o1[102]
  PIN o1[103]
    DIRECTION OUTPUT ;
    USE SIGNAL ;
    PORT
      LAYER M5 ;
        RECT  46.128 0 46.152 0.192 ;
    END
  END o1[103]
  PIN o1[104]
    DIRECTION OUTPUT ;
    USE SIGNAL ;
    PORT
      LAYER M5 ;
        RECT  46.32 0 46.344 0.192 ;
    END
  END o1[104]
  PIN o1[105]
    DIRECTION OUTPUT ;
    USE SIGNAL ;
    PORT
      LAYER M5 ;
        RECT  46.464 0 46.488 0.192 ;
    END
  END o1[105]
  PIN o1[106]
    DIRECTION OUTPUT ;
    USE SIGNAL ;
    PORT
      LAYER M5 ;
        RECT  46.656 0 46.68 0.192 ;
    END
  END o1[106]
  PIN o1[107]
    DIRECTION OUTPUT ;
    USE SIGNAL ;
    PORT
      LAYER M5 ;
        RECT  46.8 0 46.824 0.192 ;
    END
  END o1[107]
  PIN o1[108]
    DIRECTION OUTPUT ;
    USE SIGNAL ;
    PORT
      LAYER M5 ;
        RECT  46.992 0 47.016 0.192 ;
    END
  END o1[108]
  PIN o1[109]
    DIRECTION OUTPUT ;
    USE SIGNAL ;
    PORT
      LAYER M5 ;
        RECT  47.184 0 47.208 0.192 ;
    END
  END o1[109]
  PIN o1[10]
    DIRECTION OUTPUT ;
    USE SIGNAL ;
    PORT
      LAYER M5 ;
        RECT  30 0 30.024 0.192 ;
    END
  END o1[10]
  PIN o1[110]
    DIRECTION OUTPUT ;
    USE SIGNAL ;
    PORT
      LAYER M5 ;
        RECT  47.328 0 47.352 0.192 ;
    END
  END o1[110]
  PIN o1[111]
    DIRECTION OUTPUT ;
    USE SIGNAL ;
    PORT
      LAYER M5 ;
        RECT  47.52 0 47.544 0.192 ;
    END
  END o1[111]
  PIN o1[112]
    DIRECTION OUTPUT ;
    USE SIGNAL ;
    PORT
      LAYER M5 ;
        RECT  47.664 0 47.688 0.192 ;
    END
  END o1[112]
  PIN o1[113]
    DIRECTION OUTPUT ;
    USE SIGNAL ;
    PORT
      LAYER M5 ;
        RECT  47.856 0 47.88 0.192 ;
    END
  END o1[113]
  PIN o1[114]
    DIRECTION OUTPUT ;
    USE SIGNAL ;
    PORT
      LAYER M5 ;
        RECT  48 0 48.024 0.192 ;
    END
  END o1[114]
  PIN o1[115]
    DIRECTION OUTPUT ;
    USE SIGNAL ;
    PORT
      LAYER M5 ;
        RECT  48.192 0 48.216 0.192 ;
    END
  END o1[115]
  PIN o1[116]
    DIRECTION OUTPUT ;
    USE SIGNAL ;
    PORT
      LAYER M5 ;
        RECT  48.384 0 48.408 0.192 ;
    END
  END o1[116]
  PIN o1[117]
    DIRECTION OUTPUT ;
    USE SIGNAL ;
    PORT
      LAYER M5 ;
        RECT  48.528 0 48.552 0.192 ;
    END
  END o1[117]
  PIN o1[118]
    DIRECTION OUTPUT ;
    USE SIGNAL ;
    PORT
      LAYER M5 ;
        RECT  48.72 0 48.744 0.192 ;
    END
  END o1[118]
  PIN o1[119]
    DIRECTION OUTPUT ;
    USE SIGNAL ;
    PORT
      LAYER M5 ;
        RECT  48.864 0 48.888 0.192 ;
    END
  END o1[119]
  PIN o1[11]
    DIRECTION OUTPUT ;
    USE SIGNAL ;
    PORT
      LAYER M5 ;
        RECT  30.144 0 30.168 0.192 ;
    END
  END o1[11]
  PIN o1[120]
    DIRECTION OUTPUT ;
    USE SIGNAL ;
    PORT
      LAYER M5 ;
        RECT  49.056 0 49.08 0.192 ;
    END
  END o1[120]
  PIN o1[121]
    DIRECTION OUTPUT ;
    USE SIGNAL ;
    PORT
      LAYER M5 ;
        RECT  49.2 0 49.224 0.192 ;
    END
  END o1[121]
  PIN o1[122]
    DIRECTION OUTPUT ;
    USE SIGNAL ;
    PORT
      LAYER M5 ;
        RECT  49.392 0 49.416 0.192 ;
    END
  END o1[122]
  PIN o1[123]
    DIRECTION OUTPUT ;
    USE SIGNAL ;
    PORT
      LAYER M5 ;
        RECT  49.584 0 49.608 0.192 ;
    END
  END o1[123]
  PIN o1[124]
    DIRECTION OUTPUT ;
    USE SIGNAL ;
    PORT
      LAYER M5 ;
        RECT  49.728 0 49.752 0.192 ;
    END
  END o1[124]
  PIN o1[125]
    DIRECTION OUTPUT ;
    USE SIGNAL ;
    PORT
      LAYER M5 ;
        RECT  49.92 0 49.944 0.192 ;
    END
  END o1[125]
  PIN o1[126]
    DIRECTION OUTPUT ;
    USE SIGNAL ;
    PORT
      LAYER M5 ;
        RECT  50.064 0 50.088 0.192 ;
    END
  END o1[126]
  PIN o1[127]
    DIRECTION OUTPUT ;
    USE SIGNAL ;
    PORT
      LAYER M5 ;
        RECT  50.256 0 50.28 0.192 ;
    END
  END o1[127]
  PIN o1[128]
    DIRECTION OUTPUT ;
    USE SIGNAL ;
    PORT
      LAYER M5 ;
        RECT  50.448 0 50.472 0.192 ;
    END
  END o1[128]
  PIN o1[129]
    DIRECTION OUTPUT ;
    USE SIGNAL ;
    PORT
      LAYER M5 ;
        RECT  50.592 0 50.616 0.192 ;
    END
  END o1[129]
  PIN o1[12]
    DIRECTION OUTPUT ;
    USE SIGNAL ;
    PORT
      LAYER M5 ;
        RECT  30.336 0 30.36 0.192 ;
    END
  END o1[12]
  PIN o1[130]
    DIRECTION OUTPUT ;
    USE SIGNAL ;
    PORT
      LAYER M5 ;
        RECT  50.784 0 50.808 0.192 ;
    END
  END o1[130]
  PIN o1[131]
    DIRECTION OUTPUT ;
    USE SIGNAL ;
    PORT
      LAYER M5 ;
        RECT  50.928 0 50.952 0.192 ;
    END
  END o1[131]
  PIN o1[132]
    DIRECTION OUTPUT ;
    USE SIGNAL ;
    PORT
      LAYER M5 ;
        RECT  51.12 0 51.144 0.192 ;
    END
  END o1[132]
  PIN o1[133]
    DIRECTION OUTPUT ;
    USE SIGNAL ;
    PORT
      LAYER M5 ;
        RECT  51.264 0 51.288 0.192 ;
    END
  END o1[133]
  PIN o1[134]
    DIRECTION OUTPUT ;
    USE SIGNAL ;
    PORT
      LAYER M5 ;
        RECT  51.456 0 51.48 0.192 ;
    END
  END o1[134]
  PIN o1[135]
    DIRECTION OUTPUT ;
    USE SIGNAL ;
    PORT
      LAYER M5 ;
        RECT  51.648 0 51.672 0.192 ;
    END
  END o1[135]
  PIN o1[13]
    DIRECTION OUTPUT ;
    USE SIGNAL ;
    PORT
      LAYER M5 ;
        RECT  30.48 0 30.504 0.192 ;
    END
  END o1[13]
  PIN o1[14]
    DIRECTION OUTPUT ;
    USE SIGNAL ;
    PORT
      LAYER M5 ;
        RECT  30.672 0 30.696 0.192 ;
    END
  END o1[14]
  PIN o1[15]
    DIRECTION OUTPUT ;
    USE SIGNAL ;
    PORT
      LAYER M5 ;
        RECT  30.864 0 30.888 0.192 ;
    END
  END o1[15]
  PIN o1[16]
    DIRECTION OUTPUT ;
    USE SIGNAL ;
    PORT
      LAYER M5 ;
        RECT  31.008 0 31.032 0.192 ;
    END
  END o1[16]
  PIN o1[17]
    DIRECTION OUTPUT ;
    USE SIGNAL ;
    PORT
      LAYER M5 ;
        RECT  31.2 0 31.224 0.192 ;
    END
  END o1[17]
  PIN o1[18]
    DIRECTION OUTPUT ;
    USE SIGNAL ;
    PORT
      LAYER M5 ;
        RECT  31.344 0 31.368 0.192 ;
    END
  END o1[18]
  PIN o1[19]
    DIRECTION OUTPUT ;
    USE SIGNAL ;
    PORT
      LAYER M5 ;
        RECT  31.536 0 31.56 0.192 ;
    END
  END o1[19]
  PIN o1[1]
    DIRECTION OUTPUT ;
    USE SIGNAL ;
    PORT
      LAYER M5 ;
        RECT  28.416 0 28.44 0.192 ;
    END
  END o1[1]
  PIN o1[20]
    DIRECTION OUTPUT ;
    USE SIGNAL ;
    PORT
      LAYER M5 ;
        RECT  31.68 0 31.704 0.192 ;
    END
  END o1[20]
  PIN o1[21]
    DIRECTION OUTPUT ;
    USE SIGNAL ;
    PORT
      LAYER M5 ;
        RECT  31.872 0 31.896 0.192 ;
    END
  END o1[21]
  PIN o1[22]
    DIRECTION OUTPUT ;
    USE SIGNAL ;
    PORT
      LAYER M5 ;
        RECT  32.064 0 32.088 0.192 ;
    END
  END o1[22]
  PIN o1[23]
    DIRECTION OUTPUT ;
    USE SIGNAL ;
    PORT
      LAYER M5 ;
        RECT  32.208 0 32.232 0.192 ;
    END
  END o1[23]
  PIN o1[24]
    DIRECTION OUTPUT ;
    USE SIGNAL ;
    PORT
      LAYER M5 ;
        RECT  32.4 0 32.424 0.192 ;
    END
  END o1[24]
  PIN o1[25]
    DIRECTION OUTPUT ;
    USE SIGNAL ;
    PORT
      LAYER M5 ;
        RECT  32.544 0 32.568 0.192 ;
    END
  END o1[25]
  PIN o1[26]
    DIRECTION OUTPUT ;
    USE SIGNAL ;
    PORT
      LAYER M5 ;
        RECT  32.736 0 32.76 0.192 ;
    END
  END o1[26]
  PIN o1[27]
    DIRECTION OUTPUT ;
    USE SIGNAL ;
    PORT
      LAYER M5 ;
        RECT  32.928 0 32.952 0.192 ;
    END
  END o1[27]
  PIN o1[28]
    DIRECTION OUTPUT ;
    USE SIGNAL ;
    PORT
      LAYER M5 ;
        RECT  33.072 0 33.096 0.192 ;
    END
  END o1[28]
  PIN o1[29]
    DIRECTION OUTPUT ;
    USE SIGNAL ;
    PORT
      LAYER M5 ;
        RECT  33.264 0 33.288 0.192 ;
    END
  END o1[29]
  PIN o1[2]
    DIRECTION OUTPUT ;
    USE SIGNAL ;
    PORT
      LAYER M5 ;
        RECT  28.608 0 28.632 0.192 ;
    END
  END o1[2]
  PIN o1[30]
    DIRECTION OUTPUT ;
    USE SIGNAL ;
    PORT
      LAYER M5 ;
        RECT  33.408 0 33.432 0.192 ;
    END
  END o1[30]
  PIN o1[31]
    DIRECTION OUTPUT ;
    USE SIGNAL ;
    PORT
      LAYER M5 ;
        RECT  33.6 0 33.624 0.192 ;
    END
  END o1[31]
  PIN o1[32]
    DIRECTION OUTPUT ;
    USE SIGNAL ;
    PORT
      LAYER M5 ;
        RECT  33.744 0 33.768 0.192 ;
    END
  END o1[32]
  PIN o1[33]
    DIRECTION OUTPUT ;
    USE SIGNAL ;
    PORT
      LAYER M5 ;
        RECT  33.936 0 33.96 0.192 ;
    END
  END o1[33]
  PIN o1[34]
    DIRECTION OUTPUT ;
    USE SIGNAL ;
    PORT
      LAYER M5 ;
        RECT  34.128 0 34.152 0.192 ;
    END
  END o1[34]
  PIN o1[35]
    DIRECTION OUTPUT ;
    USE SIGNAL ;
    PORT
      LAYER M5 ;
        RECT  34.272 0 34.296 0.192 ;
    END
  END o1[35]
  PIN o1[36]
    DIRECTION OUTPUT ;
    USE SIGNAL ;
    PORT
      LAYER M5 ;
        RECT  34.464 0 34.488 0.192 ;
    END
  END o1[36]
  PIN o1[37]
    DIRECTION OUTPUT ;
    USE SIGNAL ;
    PORT
      LAYER M5 ;
        RECT  34.608 0 34.632 0.192 ;
    END
  END o1[37]
  PIN o1[38]
    DIRECTION OUTPUT ;
    USE SIGNAL ;
    PORT
      LAYER M5 ;
        RECT  34.8 0 34.824 0.192 ;
    END
  END o1[38]
  PIN o1[39]
    DIRECTION OUTPUT ;
    USE SIGNAL ;
    PORT
      LAYER M5 ;
        RECT  34.944 0 34.968 0.192 ;
    END
  END o1[39]
  PIN o1[3]
    DIRECTION OUTPUT ;
    USE SIGNAL ;
    PORT
      LAYER M5 ;
        RECT  28.8 0 28.824 0.192 ;
    END
  END o1[3]
  PIN o1[40]
    DIRECTION OUTPUT ;
    USE SIGNAL ;
    PORT
      LAYER M5 ;
        RECT  35.136 0 35.16 0.192 ;
    END
  END o1[40]
  PIN o1[41]
    DIRECTION OUTPUT ;
    USE SIGNAL ;
    PORT
      LAYER M5 ;
        RECT  35.328 0 35.352 0.192 ;
    END
  END o1[41]
  PIN o1[42]
    DIRECTION OUTPUT ;
    USE SIGNAL ;
    PORT
      LAYER M5 ;
        RECT  35.472 0 35.496 0.192 ;
    END
  END o1[42]
  PIN o1[43]
    DIRECTION OUTPUT ;
    USE SIGNAL ;
    PORT
      LAYER M5 ;
        RECT  35.664 0 35.688 0.192 ;
    END
  END o1[43]
  PIN o1[44]
    DIRECTION OUTPUT ;
    USE SIGNAL ;
    PORT
      LAYER M5 ;
        RECT  35.808 0 35.832 0.192 ;
    END
  END o1[44]
  PIN o1[45]
    DIRECTION OUTPUT ;
    USE SIGNAL ;
    PORT
      LAYER M5 ;
        RECT  36 0 36.024 0.192 ;
    END
  END o1[45]
  PIN o1[46]
    DIRECTION OUTPUT ;
    USE SIGNAL ;
    PORT
      LAYER M5 ;
        RECT  36.192 0 36.216 0.192 ;
    END
  END o1[46]
  PIN o1[47]
    DIRECTION OUTPUT ;
    USE SIGNAL ;
    PORT
      LAYER M5 ;
        RECT  36.336 0 36.36 0.192 ;
    END
  END o1[47]
  PIN o1[48]
    DIRECTION OUTPUT ;
    USE SIGNAL ;
    PORT
      LAYER M5 ;
        RECT  36.528 0 36.552 0.192 ;
    END
  END o1[48]
  PIN o1[49]
    DIRECTION OUTPUT ;
    USE SIGNAL ;
    PORT
      LAYER M5 ;
        RECT  36.672 0 36.696 0.192 ;
    END
  END o1[49]
  PIN o1[4]
    DIRECTION OUTPUT ;
    USE SIGNAL ;
    PORT
      LAYER M5 ;
        RECT  28.944 0 28.968 0.192 ;
    END
  END o1[4]
  PIN o1[50]
    DIRECTION OUTPUT ;
    USE SIGNAL ;
    PORT
      LAYER M5 ;
        RECT  36.864 0 36.888 0.192 ;
    END
  END o1[50]
  PIN o1[51]
    DIRECTION OUTPUT ;
    USE SIGNAL ;
    PORT
      LAYER M5 ;
        RECT  37.008 0 37.032 0.192 ;
    END
  END o1[51]
  PIN o1[52]
    DIRECTION OUTPUT ;
    USE SIGNAL ;
    PORT
      LAYER M5 ;
        RECT  37.2 0 37.224 0.192 ;
    END
  END o1[52]
  PIN o1[53]
    DIRECTION OUTPUT ;
    USE SIGNAL ;
    PORT
      LAYER M5 ;
        RECT  37.392 0 37.416 0.192 ;
    END
  END o1[53]
  PIN o1[54]
    DIRECTION OUTPUT ;
    USE SIGNAL ;
    PORT
      LAYER M5 ;
        RECT  37.536 0 37.56 0.192 ;
    END
  END o1[54]
  PIN o1[55]
    DIRECTION OUTPUT ;
    USE SIGNAL ;
    PORT
      LAYER M5 ;
        RECT  37.728 0 37.752 0.192 ;
    END
  END o1[55]
  PIN o1[56]
    DIRECTION OUTPUT ;
    USE SIGNAL ;
    PORT
      LAYER M5 ;
        RECT  37.872 0 37.896 0.192 ;
    END
  END o1[56]
  PIN o1[57]
    DIRECTION OUTPUT ;
    USE SIGNAL ;
    PORT
      LAYER M5 ;
        RECT  38.064 0 38.088 0.192 ;
    END
  END o1[57]
  PIN o1[58]
    DIRECTION OUTPUT ;
    USE SIGNAL ;
    PORT
      LAYER M5 ;
        RECT  38.208 0 38.232 0.192 ;
    END
  END o1[58]
  PIN o1[59]
    DIRECTION OUTPUT ;
    USE SIGNAL ;
    PORT
      LAYER M5 ;
        RECT  38.4 0 38.424 0.192 ;
    END
  END o1[59]
  PIN o1[5]
    DIRECTION OUTPUT ;
    USE SIGNAL ;
    PORT
      LAYER M5 ;
        RECT  29.136 0 29.16 0.192 ;
    END
  END o1[5]
  PIN o1[60]
    DIRECTION OUTPUT ;
    USE SIGNAL ;
    PORT
      LAYER M5 ;
        RECT  38.592 0 38.616 0.192 ;
    END
  END o1[60]
  PIN o1[61]
    DIRECTION OUTPUT ;
    USE SIGNAL ;
    PORT
      LAYER M5 ;
        RECT  38.736 0 38.76 0.192 ;
    END
  END o1[61]
  PIN o1[62]
    DIRECTION OUTPUT ;
    USE SIGNAL ;
    PORT
      LAYER M5 ;
        RECT  38.928 0 38.952 0.192 ;
    END
  END o1[62]
  PIN o1[63]
    DIRECTION OUTPUT ;
    USE SIGNAL ;
    PORT
      LAYER M5 ;
        RECT  39.072 0 39.096 0.192 ;
    END
  END o1[63]
  PIN o1[64]
    DIRECTION OUTPUT ;
    USE SIGNAL ;
    PORT
      LAYER M5 ;
        RECT  39.264 0 39.288 0.192 ;
    END
  END o1[64]
  PIN o1[65]
    DIRECTION OUTPUT ;
    USE SIGNAL ;
    PORT
      LAYER M5 ;
        RECT  39.456 0 39.48 0.192 ;
    END
  END o1[65]
  PIN o1[66]
    DIRECTION OUTPUT ;
    USE SIGNAL ;
    PORT
      LAYER M5 ;
        RECT  39.6 0 39.624 0.192 ;
    END
  END o1[66]
  PIN o1[67]
    DIRECTION OUTPUT ;
    USE SIGNAL ;
    PORT
      LAYER M5 ;
        RECT  39.792 0 39.816 0.192 ;
    END
  END o1[67]
  PIN o1[68]
    DIRECTION OUTPUT ;
    USE SIGNAL ;
    PORT
      LAYER M5 ;
        RECT  40.128 0 40.152 0.192 ;
    END
  END o1[68]
  PIN o1[69]
    DIRECTION OUTPUT ;
    USE SIGNAL ;
    PORT
      LAYER M5 ;
        RECT  40.272 0 40.296 0.192 ;
    END
  END o1[69]
  PIN o1[6]
    DIRECTION OUTPUT ;
    USE SIGNAL ;
    PORT
      LAYER M5 ;
        RECT  29.28 0 29.304 0.192 ;
    END
  END o1[6]
  PIN o1[70]
    DIRECTION OUTPUT ;
    USE SIGNAL ;
    PORT
      LAYER M5 ;
        RECT  40.464 0 40.488 0.192 ;
    END
  END o1[70]
  PIN o1[71]
    DIRECTION OUTPUT ;
    USE SIGNAL ;
    PORT
      LAYER M5 ;
        RECT  40.656 0 40.68 0.192 ;
    END
  END o1[71]
  PIN o1[72]
    DIRECTION OUTPUT ;
    USE SIGNAL ;
    PORT
      LAYER M5 ;
        RECT  40.8 0 40.824 0.192 ;
    END
  END o1[72]
  PIN o1[73]
    DIRECTION OUTPUT ;
    USE SIGNAL ;
    PORT
      LAYER M5 ;
        RECT  40.992 0 41.016 0.192 ;
    END
  END o1[73]
  PIN o1[74]
    DIRECTION OUTPUT ;
    USE SIGNAL ;
    PORT
      LAYER M5 ;
        RECT  41.136 0 41.16 0.192 ;
    END
  END o1[74]
  PIN o1[75]
    DIRECTION OUTPUT ;
    USE SIGNAL ;
    PORT
      LAYER M5 ;
        RECT  41.328 0 41.352 0.192 ;
    END
  END o1[75]
  PIN o1[76]
    DIRECTION OUTPUT ;
    USE SIGNAL ;
    PORT
      LAYER M5 ;
        RECT  41.472 0 41.496 0.192 ;
    END
  END o1[76]
  PIN o1[77]
    DIRECTION OUTPUT ;
    USE SIGNAL ;
    PORT
      LAYER M5 ;
        RECT  41.664 0 41.688 0.192 ;
    END
  END o1[77]
  PIN o1[78]
    DIRECTION OUTPUT ;
    USE SIGNAL ;
    PORT
      LAYER M5 ;
        RECT  41.856 0 41.88 0.192 ;
    END
  END o1[78]
  PIN o1[79]
    DIRECTION OUTPUT ;
    USE SIGNAL ;
    PORT
      LAYER M5 ;
        RECT  42 0 42.024 0.192 ;
    END
  END o1[79]
  PIN o1[7]
    DIRECTION OUTPUT ;
    USE SIGNAL ;
    PORT
      LAYER M5 ;
        RECT  29.472 0 29.496 0.192 ;
    END
  END o1[7]
  PIN o1[80]
    DIRECTION OUTPUT ;
    USE SIGNAL ;
    PORT
      LAYER M5 ;
        RECT  42.192 0 42.216 0.192 ;
    END
  END o1[80]
  PIN o1[81]
    DIRECTION OUTPUT ;
    USE SIGNAL ;
    PORT
      LAYER M5 ;
        RECT  42.336 0 42.36 0.192 ;
    END
  END o1[81]
  PIN o1[82]
    DIRECTION OUTPUT ;
    USE SIGNAL ;
    PORT
      LAYER M5 ;
        RECT  42.528 0 42.552 0.192 ;
    END
  END o1[82]
  PIN o1[83]
    DIRECTION OUTPUT ;
    USE SIGNAL ;
    PORT
      LAYER M5 ;
        RECT  42.72 0 42.744 0.192 ;
    END
  END o1[83]
  PIN o1[84]
    DIRECTION OUTPUT ;
    USE SIGNAL ;
    PORT
      LAYER M5 ;
        RECT  42.864 0 42.888 0.192 ;
    END
  END o1[84]
  PIN o1[85]
    DIRECTION OUTPUT ;
    USE SIGNAL ;
    PORT
      LAYER M5 ;
        RECT  43.056 0 43.08 0.192 ;
    END
  END o1[85]
  PIN o1[86]
    DIRECTION OUTPUT ;
    USE SIGNAL ;
    PORT
      LAYER M5 ;
        RECT  43.2 0 43.224 0.192 ;
    END
  END o1[86]
  PIN o1[87]
    DIRECTION OUTPUT ;
    USE SIGNAL ;
    PORT
      LAYER M5 ;
        RECT  43.392 0 43.416 0.192 ;
    END
  END o1[87]
  PIN o1[88]
    DIRECTION OUTPUT ;
    USE SIGNAL ;
    PORT
      LAYER M5 ;
        RECT  43.536 0 43.56 0.192 ;
    END
  END o1[88]
  PIN o1[89]
    DIRECTION OUTPUT ;
    USE SIGNAL ;
    PORT
      LAYER M5 ;
        RECT  43.728 0 43.752 0.192 ;
    END
  END o1[89]
  PIN o1[8]
    DIRECTION OUTPUT ;
    USE SIGNAL ;
    PORT
      LAYER M5 ;
        RECT  29.664 0 29.688 0.192 ;
    END
  END o1[8]
  PIN o1[90]
    DIRECTION OUTPUT ;
    USE SIGNAL ;
    PORT
      LAYER M5 ;
        RECT  43.92 0 43.944 0.192 ;
    END
  END o1[90]
  PIN o1[91]
    DIRECTION OUTPUT ;
    USE SIGNAL ;
    PORT
      LAYER M5 ;
        RECT  44.064 0 44.088 0.192 ;
    END
  END o1[91]
  PIN o1[92]
    DIRECTION OUTPUT ;
    USE SIGNAL ;
    PORT
      LAYER M5 ;
        RECT  44.256 0 44.28 0.192 ;
    END
  END o1[92]
  PIN o1[93]
    DIRECTION OUTPUT ;
    USE SIGNAL ;
    PORT
      LAYER M5 ;
        RECT  44.4 0 44.424 0.192 ;
    END
  END o1[93]
  PIN o1[94]
    DIRECTION OUTPUT ;
    USE SIGNAL ;
    PORT
      LAYER M5 ;
        RECT  44.592 0 44.616 0.192 ;
    END
  END o1[94]
  PIN o1[95]
    DIRECTION OUTPUT ;
    USE SIGNAL ;
    PORT
      LAYER M5 ;
        RECT  44.736 0 44.76 0.192 ;
    END
  END o1[95]
  PIN o1[96]
    DIRECTION OUTPUT ;
    USE SIGNAL ;
    PORT
      LAYER M5 ;
        RECT  44.928 0 44.952 0.192 ;
    END
  END o1[96]
  PIN o1[97]
    DIRECTION OUTPUT ;
    USE SIGNAL ;
    PORT
      LAYER M5 ;
        RECT  45.12 0 45.144 0.192 ;
    END
  END o1[97]
  PIN o1[98]
    DIRECTION OUTPUT ;
    USE SIGNAL ;
    PORT
      LAYER M5 ;
        RECT  45.264 0 45.288 0.192 ;
    END
  END o1[98]
  PIN o1[99]
    DIRECTION OUTPUT ;
    USE SIGNAL ;
    PORT
      LAYER M5 ;
        RECT  45.456 0 45.48 0.192 ;
    END
  END o1[99]
  PIN o1[9]
    DIRECTION OUTPUT ;
    USE SIGNAL ;
    PORT
      LAYER M5 ;
        RECT  29.808 0 29.832 0.192 ;
    END
  END o1[9]
  PIN o2[0]
    DIRECTION OUTPUT ;
    USE SIGNAL ;
    PORT
      LAYER M5 ;
        RECT  28.272 21.408 28.296 21.6 ;
    END
  END o2[0]
  PIN o2[100]
    DIRECTION OUTPUT ;
    USE SIGNAL ;
    PORT
      LAYER M5 ;
        RECT  45.6 21.408 45.624 21.6 ;
    END
  END o2[100]
  PIN o2[101]
    DIRECTION OUTPUT ;
    USE SIGNAL ;
    PORT
      LAYER M5 ;
        RECT  45.792 21.408 45.816 21.6 ;
    END
  END o2[101]
  PIN o2[102]
    DIRECTION OUTPUT ;
    USE SIGNAL ;
    PORT
      LAYER M5 ;
        RECT  45.936 21.408 45.96 21.6 ;
    END
  END o2[102]
  PIN o2[103]
    DIRECTION OUTPUT ;
    USE SIGNAL ;
    PORT
      LAYER M5 ;
        RECT  46.128 21.408 46.152 21.6 ;
    END
  END o2[103]
  PIN o2[104]
    DIRECTION OUTPUT ;
    USE SIGNAL ;
    PORT
      LAYER M5 ;
        RECT  46.32 21.408 46.344 21.6 ;
    END
  END o2[104]
  PIN o2[105]
    DIRECTION OUTPUT ;
    USE SIGNAL ;
    PORT
      LAYER M5 ;
        RECT  46.464 21.408 46.488 21.6 ;
    END
  END o2[105]
  PIN o2[106]
    DIRECTION OUTPUT ;
    USE SIGNAL ;
    PORT
      LAYER M5 ;
        RECT  46.656 21.408 46.68 21.6 ;
    END
  END o2[106]
  PIN o2[107]
    DIRECTION OUTPUT ;
    USE SIGNAL ;
    PORT
      LAYER M5 ;
        RECT  46.8 21.408 46.824 21.6 ;
    END
  END o2[107]
  PIN o2[108]
    DIRECTION OUTPUT ;
    USE SIGNAL ;
    PORT
      LAYER M5 ;
        RECT  46.992 21.408 47.016 21.6 ;
    END
  END o2[108]
  PIN o2[109]
    DIRECTION OUTPUT ;
    USE SIGNAL ;
    PORT
      LAYER M5 ;
        RECT  47.184 21.408 47.208 21.6 ;
    END
  END o2[109]
  PIN o2[10]
    DIRECTION OUTPUT ;
    USE SIGNAL ;
    PORT
      LAYER M5 ;
        RECT  30 21.408 30.024 21.6 ;
    END
  END o2[10]
  PIN o2[110]
    DIRECTION OUTPUT ;
    USE SIGNAL ;
    PORT
      LAYER M5 ;
        RECT  47.328 21.408 47.352 21.6 ;
    END
  END o2[110]
  PIN o2[111]
    DIRECTION OUTPUT ;
    USE SIGNAL ;
    PORT
      LAYER M5 ;
        RECT  47.52 21.408 47.544 21.6 ;
    END
  END o2[111]
  PIN o2[112]
    DIRECTION OUTPUT ;
    USE SIGNAL ;
    PORT
      LAYER M5 ;
        RECT  47.664 21.408 47.688 21.6 ;
    END
  END o2[112]
  PIN o2[113]
    DIRECTION OUTPUT ;
    USE SIGNAL ;
    PORT
      LAYER M5 ;
        RECT  47.856 21.408 47.88 21.6 ;
    END
  END o2[113]
  PIN o2[114]
    DIRECTION OUTPUT ;
    USE SIGNAL ;
    PORT
      LAYER M5 ;
        RECT  48 21.408 48.024 21.6 ;
    END
  END o2[114]
  PIN o2[115]
    DIRECTION OUTPUT ;
    USE SIGNAL ;
    PORT
      LAYER M5 ;
        RECT  48.192 21.408 48.216 21.6 ;
    END
  END o2[115]
  PIN o2[116]
    DIRECTION OUTPUT ;
    USE SIGNAL ;
    PORT
      LAYER M5 ;
        RECT  48.384 21.408 48.408 21.6 ;
    END
  END o2[116]
  PIN o2[117]
    DIRECTION OUTPUT ;
    USE SIGNAL ;
    PORT
      LAYER M5 ;
        RECT  48.528 21.408 48.552 21.6 ;
    END
  END o2[117]
  PIN o2[118]
    DIRECTION OUTPUT ;
    USE SIGNAL ;
    PORT
      LAYER M5 ;
        RECT  48.72 21.408 48.744 21.6 ;
    END
  END o2[118]
  PIN o2[119]
    DIRECTION OUTPUT ;
    USE SIGNAL ;
    PORT
      LAYER M5 ;
        RECT  48.864 21.408 48.888 21.6 ;
    END
  END o2[119]
  PIN o2[11]
    DIRECTION OUTPUT ;
    USE SIGNAL ;
    PORT
      LAYER M5 ;
        RECT  30.144 21.408 30.168 21.6 ;
    END
  END o2[11]
  PIN o2[120]
    DIRECTION OUTPUT ;
    USE SIGNAL ;
    PORT
      LAYER M5 ;
        RECT  49.056 21.408 49.08 21.6 ;
    END
  END o2[120]
  PIN o2[121]
    DIRECTION OUTPUT ;
    USE SIGNAL ;
    PORT
      LAYER M5 ;
        RECT  49.2 21.408 49.224 21.6 ;
    END
  END o2[121]
  PIN o2[122]
    DIRECTION OUTPUT ;
    USE SIGNAL ;
    PORT
      LAYER M5 ;
        RECT  49.392 21.408 49.416 21.6 ;
    END
  END o2[122]
  PIN o2[123]
    DIRECTION OUTPUT ;
    USE SIGNAL ;
    PORT
      LAYER M5 ;
        RECT  49.584 21.408 49.608 21.6 ;
    END
  END o2[123]
  PIN o2[124]
    DIRECTION OUTPUT ;
    USE SIGNAL ;
    PORT
      LAYER M5 ;
        RECT  49.728 21.408 49.752 21.6 ;
    END
  END o2[124]
  PIN o2[125]
    DIRECTION OUTPUT ;
    USE SIGNAL ;
    PORT
      LAYER M5 ;
        RECT  49.92 21.408 49.944 21.6 ;
    END
  END o2[125]
  PIN o2[126]
    DIRECTION OUTPUT ;
    USE SIGNAL ;
    PORT
      LAYER M5 ;
        RECT  50.064 21.408 50.088 21.6 ;
    END
  END o2[126]
  PIN o2[127]
    DIRECTION OUTPUT ;
    USE SIGNAL ;
    PORT
      LAYER M5 ;
        RECT  50.256 21.408 50.28 21.6 ;
    END
  END o2[127]
  PIN o2[128]
    DIRECTION OUTPUT ;
    USE SIGNAL ;
    PORT
      LAYER M5 ;
        RECT  50.448 21.408 50.472 21.6 ;
    END
  END o2[128]
  PIN o2[129]
    DIRECTION OUTPUT ;
    USE SIGNAL ;
    PORT
      LAYER M5 ;
        RECT  50.592 21.408 50.616 21.6 ;
    END
  END o2[129]
  PIN o2[12]
    DIRECTION OUTPUT ;
    USE SIGNAL ;
    PORT
      LAYER M5 ;
        RECT  30.336 21.408 30.36 21.6 ;
    END
  END o2[12]
  PIN o2[130]
    DIRECTION OUTPUT ;
    USE SIGNAL ;
    PORT
      LAYER M5 ;
        RECT  50.784 21.408 50.808 21.6 ;
    END
  END o2[130]
  PIN o2[131]
    DIRECTION OUTPUT ;
    USE SIGNAL ;
    PORT
      LAYER M5 ;
        RECT  50.928 21.408 50.952 21.6 ;
    END
  END o2[131]
  PIN o2[132]
    DIRECTION OUTPUT ;
    USE SIGNAL ;
    PORT
      LAYER M5 ;
        RECT  51.12 21.408 51.144 21.6 ;
    END
  END o2[132]
  PIN o2[133]
    DIRECTION OUTPUT ;
    USE SIGNAL ;
    PORT
      LAYER M5 ;
        RECT  51.264 21.408 51.288 21.6 ;
    END
  END o2[133]
  PIN o2[134]
    DIRECTION OUTPUT ;
    USE SIGNAL ;
    PORT
      LAYER M5 ;
        RECT  51.456 21.408 51.48 21.6 ;
    END
  END o2[134]
  PIN o2[135]
    DIRECTION OUTPUT ;
    USE SIGNAL ;
    PORT
      LAYER M5 ;
        RECT  51.648 21.408 51.672 21.6 ;
    END
  END o2[135]
  PIN o2[13]
    DIRECTION OUTPUT ;
    USE SIGNAL ;
    PORT
      LAYER M5 ;
        RECT  30.48 21.408 30.504 21.6 ;
    END
  END o2[13]
  PIN o2[14]
    DIRECTION OUTPUT ;
    USE SIGNAL ;
    PORT
      LAYER M5 ;
        RECT  30.672 21.408 30.696 21.6 ;
    END
  END o2[14]
  PIN o2[15]
    DIRECTION OUTPUT ;
    USE SIGNAL ;
    PORT
      LAYER M5 ;
        RECT  30.864 21.408 30.888 21.6 ;
    END
  END o2[15]
  PIN o2[16]
    DIRECTION OUTPUT ;
    USE SIGNAL ;
    PORT
      LAYER M5 ;
        RECT  31.008 21.408 31.032 21.6 ;
    END
  END o2[16]
  PIN o2[17]
    DIRECTION OUTPUT ;
    USE SIGNAL ;
    PORT
      LAYER M5 ;
        RECT  31.2 21.408 31.224 21.6 ;
    END
  END o2[17]
  PIN o2[18]
    DIRECTION OUTPUT ;
    USE SIGNAL ;
    PORT
      LAYER M5 ;
        RECT  31.344 21.408 31.368 21.6 ;
    END
  END o2[18]
  PIN o2[19]
    DIRECTION OUTPUT ;
    USE SIGNAL ;
    PORT
      LAYER M5 ;
        RECT  31.536 21.408 31.56 21.6 ;
    END
  END o2[19]
  PIN o2[1]
    DIRECTION OUTPUT ;
    USE SIGNAL ;
    PORT
      LAYER M5 ;
        RECT  28.416 21.408 28.44 21.6 ;
    END
  END o2[1]
  PIN o2[20]
    DIRECTION OUTPUT ;
    USE SIGNAL ;
    PORT
      LAYER M5 ;
        RECT  31.68 21.408 31.704 21.6 ;
    END
  END o2[20]
  PIN o2[21]
    DIRECTION OUTPUT ;
    USE SIGNAL ;
    PORT
      LAYER M5 ;
        RECT  31.872 21.408 31.896 21.6 ;
    END
  END o2[21]
  PIN o2[22]
    DIRECTION OUTPUT ;
    USE SIGNAL ;
    PORT
      LAYER M5 ;
        RECT  32.064 21.408 32.088 21.6 ;
    END
  END o2[22]
  PIN o2[23]
    DIRECTION OUTPUT ;
    USE SIGNAL ;
    PORT
      LAYER M5 ;
        RECT  32.208 21.408 32.232 21.6 ;
    END
  END o2[23]
  PIN o2[24]
    DIRECTION OUTPUT ;
    USE SIGNAL ;
    PORT
      LAYER M5 ;
        RECT  32.4 21.408 32.424 21.6 ;
    END
  END o2[24]
  PIN o2[25]
    DIRECTION OUTPUT ;
    USE SIGNAL ;
    PORT
      LAYER M5 ;
        RECT  32.544 21.408 32.568 21.6 ;
    END
  END o2[25]
  PIN o2[26]
    DIRECTION OUTPUT ;
    USE SIGNAL ;
    PORT
      LAYER M5 ;
        RECT  32.736 21.408 32.76 21.6 ;
    END
  END o2[26]
  PIN o2[27]
    DIRECTION OUTPUT ;
    USE SIGNAL ;
    PORT
      LAYER M5 ;
        RECT  32.928 21.408 32.952 21.6 ;
    END
  END o2[27]
  PIN o2[28]
    DIRECTION OUTPUT ;
    USE SIGNAL ;
    PORT
      LAYER M5 ;
        RECT  33.072 21.408 33.096 21.6 ;
    END
  END o2[28]
  PIN o2[29]
    DIRECTION OUTPUT ;
    USE SIGNAL ;
    PORT
      LAYER M5 ;
        RECT  33.264 21.408 33.288 21.6 ;
    END
  END o2[29]
  PIN o2[2]
    DIRECTION OUTPUT ;
    USE SIGNAL ;
    PORT
      LAYER M5 ;
        RECT  28.608 21.408 28.632 21.6 ;
    END
  END o2[2]
  PIN o2[30]
    DIRECTION OUTPUT ;
    USE SIGNAL ;
    PORT
      LAYER M5 ;
        RECT  33.408 21.408 33.432 21.6 ;
    END
  END o2[30]
  PIN o2[31]
    DIRECTION OUTPUT ;
    USE SIGNAL ;
    PORT
      LAYER M5 ;
        RECT  33.6 21.408 33.624 21.6 ;
    END
  END o2[31]
  PIN o2[32]
    DIRECTION OUTPUT ;
    USE SIGNAL ;
    PORT
      LAYER M5 ;
        RECT  33.744 21.408 33.768 21.6 ;
    END
  END o2[32]
  PIN o2[33]
    DIRECTION OUTPUT ;
    USE SIGNAL ;
    PORT
      LAYER M5 ;
        RECT  33.936 21.408 33.96 21.6 ;
    END
  END o2[33]
  PIN o2[34]
    DIRECTION OUTPUT ;
    USE SIGNAL ;
    PORT
      LAYER M5 ;
        RECT  34.128 21.408 34.152 21.6 ;
    END
  END o2[34]
  PIN o2[35]
    DIRECTION OUTPUT ;
    USE SIGNAL ;
    PORT
      LAYER M5 ;
        RECT  34.272 21.408 34.296 21.6 ;
    END
  END o2[35]
  PIN o2[36]
    DIRECTION OUTPUT ;
    USE SIGNAL ;
    PORT
      LAYER M5 ;
        RECT  34.464 21.408 34.488 21.6 ;
    END
  END o2[36]
  PIN o2[37]
    DIRECTION OUTPUT ;
    USE SIGNAL ;
    PORT
      LAYER M5 ;
        RECT  34.608 21.408 34.632 21.6 ;
    END
  END o2[37]
  PIN o2[38]
    DIRECTION OUTPUT ;
    USE SIGNAL ;
    PORT
      LAYER M5 ;
        RECT  34.8 21.408 34.824 21.6 ;
    END
  END o2[38]
  PIN o2[39]
    DIRECTION OUTPUT ;
    USE SIGNAL ;
    PORT
      LAYER M5 ;
        RECT  34.944 21.408 34.968 21.6 ;
    END
  END o2[39]
  PIN o2[3]
    DIRECTION OUTPUT ;
    USE SIGNAL ;
    PORT
      LAYER M5 ;
        RECT  28.8 21.408 28.824 21.6 ;
    END
  END o2[3]
  PIN o2[40]
    DIRECTION OUTPUT ;
    USE SIGNAL ;
    PORT
      LAYER M5 ;
        RECT  35.136 21.408 35.16 21.6 ;
    END
  END o2[40]
  PIN o2[41]
    DIRECTION OUTPUT ;
    USE SIGNAL ;
    PORT
      LAYER M5 ;
        RECT  35.328 21.408 35.352 21.6 ;
    END
  END o2[41]
  PIN o2[42]
    DIRECTION OUTPUT ;
    USE SIGNAL ;
    PORT
      LAYER M5 ;
        RECT  35.472 21.408 35.496 21.6 ;
    END
  END o2[42]
  PIN o2[43]
    DIRECTION OUTPUT ;
    USE SIGNAL ;
    PORT
      LAYER M5 ;
        RECT  35.664 21.408 35.688 21.6 ;
    END
  END o2[43]
  PIN o2[44]
    DIRECTION OUTPUT ;
    USE SIGNAL ;
    PORT
      LAYER M5 ;
        RECT  35.808 21.408 35.832 21.6 ;
    END
  END o2[44]
  PIN o2[45]
    DIRECTION OUTPUT ;
    USE SIGNAL ;
    PORT
      LAYER M5 ;
        RECT  36 21.408 36.024 21.6 ;
    END
  END o2[45]
  PIN o2[46]
    DIRECTION OUTPUT ;
    USE SIGNAL ;
    PORT
      LAYER M5 ;
        RECT  36.192 21.408 36.216 21.6 ;
    END
  END o2[46]
  PIN o2[47]
    DIRECTION OUTPUT ;
    USE SIGNAL ;
    PORT
      LAYER M5 ;
        RECT  36.336 21.408 36.36 21.6 ;
    END
  END o2[47]
  PIN o2[48]
    DIRECTION OUTPUT ;
    USE SIGNAL ;
    PORT
      LAYER M5 ;
        RECT  36.528 21.408 36.552 21.6 ;
    END
  END o2[48]
  PIN o2[49]
    DIRECTION OUTPUT ;
    USE SIGNAL ;
    PORT
      LAYER M5 ;
        RECT  36.672 21.408 36.696 21.6 ;
    END
  END o2[49]
  PIN o2[4]
    DIRECTION OUTPUT ;
    USE SIGNAL ;
    PORT
      LAYER M5 ;
        RECT  28.944 21.408 28.968 21.6 ;
    END
  END o2[4]
  PIN o2[50]
    DIRECTION OUTPUT ;
    USE SIGNAL ;
    PORT
      LAYER M5 ;
        RECT  36.864 21.408 36.888 21.6 ;
    END
  END o2[50]
  PIN o2[51]
    DIRECTION OUTPUT ;
    USE SIGNAL ;
    PORT
      LAYER M5 ;
        RECT  37.008 21.408 37.032 21.6 ;
    END
  END o2[51]
  PIN o2[52]
    DIRECTION OUTPUT ;
    USE SIGNAL ;
    PORT
      LAYER M5 ;
        RECT  37.2 21.408 37.224 21.6 ;
    END
  END o2[52]
  PIN o2[53]
    DIRECTION OUTPUT ;
    USE SIGNAL ;
    PORT
      LAYER M5 ;
        RECT  37.392 21.408 37.416 21.6 ;
    END
  END o2[53]
  PIN o2[54]
    DIRECTION OUTPUT ;
    USE SIGNAL ;
    PORT
      LAYER M5 ;
        RECT  37.536 21.408 37.56 21.6 ;
    END
  END o2[54]
  PIN o2[55]
    DIRECTION OUTPUT ;
    USE SIGNAL ;
    PORT
      LAYER M5 ;
        RECT  37.728 21.408 37.752 21.6 ;
    END
  END o2[55]
  PIN o2[56]
    DIRECTION OUTPUT ;
    USE SIGNAL ;
    PORT
      LAYER M5 ;
        RECT  37.872 21.408 37.896 21.6 ;
    END
  END o2[56]
  PIN o2[57]
    DIRECTION OUTPUT ;
    USE SIGNAL ;
    PORT
      LAYER M5 ;
        RECT  38.064 21.408 38.088 21.6 ;
    END
  END o2[57]
  PIN o2[58]
    DIRECTION OUTPUT ;
    USE SIGNAL ;
    PORT
      LAYER M5 ;
        RECT  38.208 21.408 38.232 21.6 ;
    END
  END o2[58]
  PIN o2[59]
    DIRECTION OUTPUT ;
    USE SIGNAL ;
    PORT
      LAYER M5 ;
        RECT  38.4 21.408 38.424 21.6 ;
    END
  END o2[59]
  PIN o2[5]
    DIRECTION OUTPUT ;
    USE SIGNAL ;
    PORT
      LAYER M5 ;
        RECT  29.136 21.408 29.16 21.6 ;
    END
  END o2[5]
  PIN o2[60]
    DIRECTION OUTPUT ;
    USE SIGNAL ;
    PORT
      LAYER M5 ;
        RECT  38.592 21.408 38.616 21.6 ;
    END
  END o2[60]
  PIN o2[61]
    DIRECTION OUTPUT ;
    USE SIGNAL ;
    PORT
      LAYER M5 ;
        RECT  38.736 21.408 38.76 21.6 ;
    END
  END o2[61]
  PIN o2[62]
    DIRECTION OUTPUT ;
    USE SIGNAL ;
    PORT
      LAYER M5 ;
        RECT  38.928 21.408 38.952 21.6 ;
    END
  END o2[62]
  PIN o2[63]
    DIRECTION OUTPUT ;
    USE SIGNAL ;
    PORT
      LAYER M5 ;
        RECT  39.072 21.408 39.096 21.6 ;
    END
  END o2[63]
  PIN o2[64]
    DIRECTION OUTPUT ;
    USE SIGNAL ;
    PORT
      LAYER M5 ;
        RECT  39.264 21.408 39.288 21.6 ;
    END
  END o2[64]
  PIN o2[65]
    DIRECTION OUTPUT ;
    USE SIGNAL ;
    PORT
      LAYER M5 ;
        RECT  39.456 21.408 39.48 21.6 ;
    END
  END o2[65]
  PIN o2[66]
    DIRECTION OUTPUT ;
    USE SIGNAL ;
    PORT
      LAYER M5 ;
        RECT  39.6 21.408 39.624 21.6 ;
    END
  END o2[66]
  PIN o2[67]
    DIRECTION OUTPUT ;
    USE SIGNAL ;
    PORT
      LAYER M5 ;
        RECT  39.792 21.408 39.816 21.6 ;
    END
  END o2[67]
  PIN o2[68]
    DIRECTION OUTPUT ;
    USE SIGNAL ;
    PORT
      LAYER M5 ;
        RECT  40.128 21.408 40.152 21.6 ;
    END
  END o2[68]
  PIN o2[69]
    DIRECTION OUTPUT ;
    USE SIGNAL ;
    PORT
      LAYER M5 ;
        RECT  40.272 21.408 40.296 21.6 ;
    END
  END o2[69]
  PIN o2[6]
    DIRECTION OUTPUT ;
    USE SIGNAL ;
    PORT
      LAYER M5 ;
        RECT  29.28 21.408 29.304 21.6 ;
    END
  END o2[6]
  PIN o2[70]
    DIRECTION OUTPUT ;
    USE SIGNAL ;
    PORT
      LAYER M5 ;
        RECT  40.464 21.408 40.488 21.6 ;
    END
  END o2[70]
  PIN o2[71]
    DIRECTION OUTPUT ;
    USE SIGNAL ;
    PORT
      LAYER M5 ;
        RECT  40.656 21.408 40.68 21.6 ;
    END
  END o2[71]
  PIN o2[72]
    DIRECTION OUTPUT ;
    USE SIGNAL ;
    PORT
      LAYER M5 ;
        RECT  40.8 21.408 40.824 21.6 ;
    END
  END o2[72]
  PIN o2[73]
    DIRECTION OUTPUT ;
    USE SIGNAL ;
    PORT
      LAYER M5 ;
        RECT  40.992 21.408 41.016 21.6 ;
    END
  END o2[73]
  PIN o2[74]
    DIRECTION OUTPUT ;
    USE SIGNAL ;
    PORT
      LAYER M5 ;
        RECT  41.136 21.408 41.16 21.6 ;
    END
  END o2[74]
  PIN o2[75]
    DIRECTION OUTPUT ;
    USE SIGNAL ;
    PORT
      LAYER M5 ;
        RECT  41.328 21.408 41.352 21.6 ;
    END
  END o2[75]
  PIN o2[76]
    DIRECTION OUTPUT ;
    USE SIGNAL ;
    PORT
      LAYER M5 ;
        RECT  41.472 21.408 41.496 21.6 ;
    END
  END o2[76]
  PIN o2[77]
    DIRECTION OUTPUT ;
    USE SIGNAL ;
    PORT
      LAYER M5 ;
        RECT  41.664 21.408 41.688 21.6 ;
    END
  END o2[77]
  PIN o2[78]
    DIRECTION OUTPUT ;
    USE SIGNAL ;
    PORT
      LAYER M5 ;
        RECT  41.856 21.408 41.88 21.6 ;
    END
  END o2[78]
  PIN o2[79]
    DIRECTION OUTPUT ;
    USE SIGNAL ;
    PORT
      LAYER M5 ;
        RECT  42 21.408 42.024 21.6 ;
    END
  END o2[79]
  PIN o2[7]
    DIRECTION OUTPUT ;
    USE SIGNAL ;
    PORT
      LAYER M5 ;
        RECT  29.472 21.408 29.496 21.6 ;
    END
  END o2[7]
  PIN o2[80]
    DIRECTION OUTPUT ;
    USE SIGNAL ;
    PORT
      LAYER M5 ;
        RECT  42.192 21.408 42.216 21.6 ;
    END
  END o2[80]
  PIN o2[81]
    DIRECTION OUTPUT ;
    USE SIGNAL ;
    PORT
      LAYER M5 ;
        RECT  42.336 21.408 42.36 21.6 ;
    END
  END o2[81]
  PIN o2[82]
    DIRECTION OUTPUT ;
    USE SIGNAL ;
    PORT
      LAYER M5 ;
        RECT  42.528 21.408 42.552 21.6 ;
    END
  END o2[82]
  PIN o2[83]
    DIRECTION OUTPUT ;
    USE SIGNAL ;
    PORT
      LAYER M5 ;
        RECT  42.72 21.408 42.744 21.6 ;
    END
  END o2[83]
  PIN o2[84]
    DIRECTION OUTPUT ;
    USE SIGNAL ;
    PORT
      LAYER M5 ;
        RECT  42.864 21.408 42.888 21.6 ;
    END
  END o2[84]
  PIN o2[85]
    DIRECTION OUTPUT ;
    USE SIGNAL ;
    PORT
      LAYER M5 ;
        RECT  43.056 21.408 43.08 21.6 ;
    END
  END o2[85]
  PIN o2[86]
    DIRECTION OUTPUT ;
    USE SIGNAL ;
    PORT
      LAYER M5 ;
        RECT  43.2 21.408 43.224 21.6 ;
    END
  END o2[86]
  PIN o2[87]
    DIRECTION OUTPUT ;
    USE SIGNAL ;
    PORT
      LAYER M5 ;
        RECT  43.392 21.408 43.416 21.6 ;
    END
  END o2[87]
  PIN o2[88]
    DIRECTION OUTPUT ;
    USE SIGNAL ;
    PORT
      LAYER M5 ;
        RECT  43.536 21.408 43.56 21.6 ;
    END
  END o2[88]
  PIN o2[89]
    DIRECTION OUTPUT ;
    USE SIGNAL ;
    PORT
      LAYER M5 ;
        RECT  43.728 21.408 43.752 21.6 ;
    END
  END o2[89]
  PIN o2[8]
    DIRECTION OUTPUT ;
    USE SIGNAL ;
    PORT
      LAYER M5 ;
        RECT  29.664 21.408 29.688 21.6 ;
    END
  END o2[8]
  PIN o2[90]
    DIRECTION OUTPUT ;
    USE SIGNAL ;
    PORT
      LAYER M5 ;
        RECT  43.92 21.408 43.944 21.6 ;
    END
  END o2[90]
  PIN o2[91]
    DIRECTION OUTPUT ;
    USE SIGNAL ;
    PORT
      LAYER M5 ;
        RECT  44.064 21.408 44.088 21.6 ;
    END
  END o2[91]
  PIN o2[92]
    DIRECTION OUTPUT ;
    USE SIGNAL ;
    PORT
      LAYER M5 ;
        RECT  44.256 21.408 44.28 21.6 ;
    END
  END o2[92]
  PIN o2[93]
    DIRECTION OUTPUT ;
    USE SIGNAL ;
    PORT
      LAYER M5 ;
        RECT  44.4 21.408 44.424 21.6 ;
    END
  END o2[93]
  PIN o2[94]
    DIRECTION OUTPUT ;
    USE SIGNAL ;
    PORT
      LAYER M5 ;
        RECT  44.592 21.408 44.616 21.6 ;
    END
  END o2[94]
  PIN o2[95]
    DIRECTION OUTPUT ;
    USE SIGNAL ;
    PORT
      LAYER M5 ;
        RECT  44.736 21.408 44.76 21.6 ;
    END
  END o2[95]
  PIN o2[96]
    DIRECTION OUTPUT ;
    USE SIGNAL ;
    PORT
      LAYER M5 ;
        RECT  44.928 21.408 44.952 21.6 ;
    END
  END o2[96]
  PIN o2[97]
    DIRECTION OUTPUT ;
    USE SIGNAL ;
    PORT
      LAYER M5 ;
        RECT  45.12 21.408 45.144 21.6 ;
    END
  END o2[97]
  PIN o2[98]
    DIRECTION OUTPUT ;
    USE SIGNAL ;
    PORT
      LAYER M5 ;
        RECT  45.264 21.408 45.288 21.6 ;
    END
  END o2[98]
  PIN o2[99]
    DIRECTION OUTPUT ;
    USE SIGNAL ;
    PORT
      LAYER M5 ;
        RECT  45.456 21.408 45.48 21.6 ;
    END
  END o2[99]
  PIN o2[9]
    DIRECTION OUTPUT ;
    USE SIGNAL ;
    PORT
      LAYER M5 ;
        RECT  29.808 21.408 29.832 21.6 ;
    END
  END o2[9]
  PIN rs
    DIRECTION INPUT ;
    USE SIGNAL ;
    PORT
      LAYER M4 ;
        RECT  0 10.8 0.192 10.824 ;
    END
  END rs
  PIN VDD
    DIRECTION INOUT ;
    USE POWER ;
    PORT
      LAYER M5 ;
        RECT  53.892 2.151 54.012 19.449 ;
        RECT  51.192 2.151 51.312 19.449 ;
        RECT  48.492 2.151 48.612 19.449 ;
        RECT  45.792 2.151 45.912 19.449 ;
        RECT  43.092 2.151 43.212 19.449 ;
        RECT  40.392 2.151 40.512 19.449 ;
        RECT  37.692 2.151 37.812 19.449 ;
        RECT  34.992 2.151 35.112 19.449 ;
        RECT  32.292 2.151 32.412 19.449 ;
        RECT  29.592 2.151 29.712 19.449 ;
        RECT  26.892 2.151 27.012 19.449 ;
        RECT  24.192 2.151 24.312 19.449 ;
        RECT  21.492 2.151 21.612 19.449 ;
        RECT  18.792 2.151 18.912 19.449 ;
        RECT  16.092 2.151 16.212 19.449 ;
        RECT  13.392 2.151 13.512 19.449 ;
        RECT  10.692 2.151 10.812 19.449 ;
        RECT  7.992 2.151 8.112 19.449 ;
        RECT  5.292 2.151 5.412 19.449 ;
        RECT  2.592 2.151 2.712 19.449 ;
    END
  END VDD
  PIN VSS
    DIRECTION INOUT ;
    USE GROUND ;
    PORT
      LAYER M5 ;
        RECT  53.7 2.137 53.82 19.463 ;
        RECT  51 2.137 51.12 19.463 ;
        RECT  48.3 2.137 48.42 19.463 ;
        RECT  45.6 2.137 45.72 19.463 ;
        RECT  42.9 2.137 43.02 19.463 ;
        RECT  40.2 2.137 40.32 19.463 ;
        RECT  37.5 2.137 37.62 19.463 ;
        RECT  34.8 2.137 34.92 19.463 ;
        RECT  32.1 2.137 32.22 19.463 ;
        RECT  29.4 2.137 29.52 19.463 ;
        RECT  26.7 2.137 26.82 19.463 ;
        RECT  24 2.137 24.12 19.463 ;
        RECT  21.3 2.137 21.42 19.463 ;
        RECT  18.6 2.137 18.72 19.463 ;
        RECT  15.9 2.137 16.02 19.463 ;
        RECT  13.2 2.137 13.32 19.463 ;
        RECT  10.5 2.137 10.62 19.463 ;
        RECT  7.8 2.137 7.92 19.463 ;
        RECT  5.1 2.137 5.22 19.463 ;
        RECT  2.4 2.137 2.52 19.463 ;
    END
  END VSS
  OBS
    LAYER RVTN ;
     RECT  2.16 2.16 54 2.295 ;
     RECT  2.16 2.565 54 2.835 ;
     RECT  2.16 3.105 54 3.375 ;
     RECT  2.16 3.645 54 3.915 ;
     RECT  2.16 4.185 54 4.455 ;
     RECT  2.16 4.725 54 4.995 ;
     RECT  2.16 5.265 54 5.535 ;
     RECT  2.16 5.805 54 6.075 ;
     RECT  2.16 6.345 54 6.615 ;
     RECT  2.16 6.885 54 7.155 ;
     RECT  2.16 7.425 54 7.695 ;
     RECT  2.16 7.965 54 8.235 ;
     RECT  2.16 8.505 54 8.775 ;
     RECT  2.16 9.045 54 9.315 ;
     RECT  2.16 9.585 54 9.855 ;
     RECT  2.16 10.125 54 10.395 ;
     RECT  2.16 10.665 54 10.935 ;
     RECT  2.16 11.205 54 11.475 ;
     RECT  2.16 11.745 54 12.015 ;
     RECT  2.16 12.285 54 12.555 ;
     RECT  2.16 12.825 54 13.095 ;
     RECT  2.16 13.365 54 13.635 ;
     RECT  2.16 13.905 54 14.175 ;
     RECT  2.16 14.445 54 14.715 ;
     RECT  2.16 14.985 54 15.255 ;
     RECT  2.16 15.525 54 15.795 ;
     RECT  2.16 16.065 54 16.335 ;
     RECT  2.16 16.605 54 16.875 ;
     RECT  2.16 17.145 54 17.415 ;
     RECT  2.16 17.685 54 17.955 ;
     RECT  2.16 18.225 54 18.495 ;
     RECT  2.16 18.765 54 19.035 ;
     RECT  2.16 19.305 54 19.44 ;
    LAYER RVTP ;
     RECT  2.16 2.295 54 2.565 ;
     RECT  2.16 2.835 54 3.105 ;
     RECT  2.16 3.375 54 3.645 ;
     RECT  2.16 3.915 54 4.185 ;
     RECT  2.16 4.455 54 4.725 ;
     RECT  2.16 4.995 54 5.265 ;
     RECT  2.16 5.535 54 5.805 ;
     RECT  2.16 6.075 54 6.345 ;
     RECT  2.16 6.615 54 6.885 ;
     RECT  2.16 7.155 54 7.425 ;
     RECT  2.16 7.695 54 7.965 ;
     RECT  2.16 8.235 54 8.505 ;
     RECT  2.16 8.775 54 9.045 ;
     RECT  2.16 9.315 54 9.585 ;
     RECT  2.16 9.855 54 10.125 ;
     RECT  2.16 10.395 54 10.665 ;
     RECT  2.16 10.935 54 11.205 ;
     RECT  2.16 11.475 54 11.745 ;
     RECT  2.16 12.015 54 12.285 ;
     RECT  2.16 12.555 54 12.825 ;
     RECT  2.16 13.095 54 13.365 ;
     RECT  2.16 13.635 54 13.905 ;
     RECT  2.16 14.175 54 14.445 ;
     RECT  2.16 14.715 54 14.985 ;
     RECT  2.16 15.255 54 15.525 ;
     RECT  2.16 15.795 54 16.065 ;
     RECT  2.16 16.335 54 16.605 ;
     RECT  2.16 16.875 54 17.145 ;
     RECT  2.16 17.415 54 17.685 ;
     RECT  2.16 17.955 54 18.225 ;
     RECT  2.16 18.495 54 18.765 ;
     RECT  2.16 19.035 54 19.305 ;
    LAYER M1 ;
     RECT  2.16 2.151 54 19.449 ;
    LAYER M2 ;
     RECT  2.16 2.151 14.071 19.449 ;
     RECT  14.071 2.106 15.179 19.449 ;
     RECT  15.179 2.151 16.951 19.449 ;
     RECT  16.951 2.151 18.823 19.494 ;
     RECT  18.823 1.728 19.499 19.494 ;
     RECT  19.499 2.151 22.639 19.494 ;
     RECT  22.639 2.151 23.863 19.53 ;
     RECT  23.863 2.034 26.231 19.53 ;
     RECT  26.231 2.106 26.699 19.53 ;
     RECT  26.699 2.151 29.119 19.53 ;
     RECT  29.119 2.106 30.695 19.53 ;
     RECT  30.695 2.151 54 19.449 ;
     RECT  54 2.421 54.012 19.179 ;
    LAYER M3 ;
     RECT  26.676 0.043 26.694 0.187 ;
     RECT  5.796 0.187 5.814 0.235 ;
     RECT  9.972 0.187 10.422 0.235 ;
     RECT  22.572 0.187 22.59 0.235 ;
     RECT  35.244 0.187 35.262 0.235 ;
     RECT  39.636 0.187 40.086 0.235 ;
     RECT  46.152 0.187 46.17 0.283 ;
     RECT  16.056 0.187 16.074 0.523 ;
     RECT  18.828 0.187 18.846 0.523 ;
     RECT  19.764 0.187 19.782 0.523 ;
     RECT  24.156 0.187 25.47 0.523 ;
     RECT  26.676 0.187 27.198 0.523 ;
     RECT  28.26 0.187 28.278 0.523 ;
     RECT  29.88 0.187 30.186 0.523 ;
     RECT  31.032 0.187 31.77 0.523 ;
     RECT  35.136 0.235 35.262 0.523 ;
     RECT  36.216 0.187 36.234 0.523 ;
     RECT  37.836 0.187 38.682 0.523 ;
     RECT  42.732 0.187 43.434 0.523 ;
     RECT  46.116 0.283 46.17 0.523 ;
     RECT  46.98 0.187 47.61 0.523 ;
     RECT  48.888 0.187 49.662 0.523 ;
     RECT  50.58 0.187 50.598 0.523 ;
     RECT  8.136 0.187 8.154 0.571 ;
     RECT  9.648 0.235 10.422 0.571 ;
     RECT  11.16 0.187 12.15 0.571 ;
     RECT  18.828 0.523 19.782 0.571 ;
     RECT  20.916 0.475 20.934 0.571 ;
     RECT  23.904 0.523 25.47 0.571 ;
     RECT  26.496 0.523 27.198 0.571 ;
     RECT  28.26 0.523 31.77 0.571 ;
     RECT  37.332 0.523 38.718 0.571 ;
     RECT  42.336 0.523 43.434 0.571 ;
     RECT  48.888 0.523 50.598 0.571 ;
     RECT  51.444 0.187 51.462 0.571 ;
     RECT  14.544 0.571 14.562 1.099 ;
     RECT  15.66 0.523 16.074 1.099 ;
     RECT  26.496 0.571 31.77 1.099 ;
     RECT  32.58 0.187 34.182 1.099 ;
     RECT  35.136 0.523 36.234 1.099 ;
     RECT  37.188 0.571 38.718 1.099 ;
     RECT  39.636 0.235 40.194 1.099 ;
     RECT  41.616 0.571 43.434 1.099 ;
     RECT  44.316 0.523 44.334 1.099 ;
     RECT  45.252 0.523 46.17 1.099 ;
     RECT  46.98 0.523 47.862 1.099 ;
     RECT  48.888 0.571 51.462 1.099 ;
     RECT  5.724 0.235 5.814 1.147 ;
     RECT  6.696 0.187 6.714 1.147 ;
     RECT  7.56 0.571 8.226 1.147 ;
     RECT  9.468 0.571 12.69 1.147 ;
     RECT  13.788 0.187 13.806 1.147 ;
     RECT  14.544 1.099 16.074 1.147 ;
     RECT  17.748 0.571 17.766 1.147 ;
     RECT  18.828 0.571 21.474 1.147 ;
     RECT  22.428 0.235 22.59 1.147 ;
     RECT  23.796 0.571 25.47 1.147 ;
     RECT  39.636 1.099 43.434 1.627 ;
     RECT  17.748 1.147 25.47 1.675 ;
     RECT  26.496 1.099 38.718 1.675 ;
     RECT  39.636 1.627 43.506 1.675 ;
     RECT  5.724 1.147 6.75 1.723 ;
     RECT  7.56 1.147 12.69 1.723 ;
     RECT  13.788 1.147 16.074 1.723 ;
     RECT  17.208 1.675 25.47 1.723 ;
     RECT  26.496 1.675 43.506 1.723 ;
     RECT  44.244 1.099 44.442 1.723 ;
     RECT  45.252 1.099 46.206 1.723 ;
     RECT  4.644 0.187 4.662 1.771 ;
     RECT  5.436 1.723 16.182 1.771 ;
     RECT  17.1 1.723 46.206 1.771 ;
     RECT  46.98 1.099 51.462 2.155 ;
     RECT  4.644 1.771 46.206 2.203 ;
     RECT  46.98 2.155 51.894 2.203 ;
     RECT  2.415 2.143 2.505 2.413 ;
     RECT  53.715 2.143 53.805 2.413 ;
     RECT  4.644 2.203 51.894 2.569 ;
     RECT  4.5 2.569 51.894 2.669 ;
     RECT  4.824 2.669 51.894 2.759 ;
     RECT  4.824 2.759 51.426 3.029 ;
     RECT  4.968 3.029 51.426 3.299 ;
     RECT  4.968 3.299 51.297 3.955 ;
     RECT  2.415 2.413 2.697 10.795 ;
     RECT  2.304 10.795 2.697 12.245 ;
     RECT  3.672 13.531 3.69 16.025 ;
     RECT  4.464 3.955 51.297 16.951 ;
     RECT  4.464 16.951 51.354 17.221 ;
     RECT  4.464 17.221 51.894 17.581 ;
     RECT  4.356 17.581 51.894 17.645 ;
     RECT  4.356 17.645 51.858 18.157 ;
     RECT  4.032 18.157 51.858 18.221 ;
     RECT  4.284 18.221 51.858 18.845 ;
     RECT  2.415 12.245 2.697 19.187 ;
     RECT  53.715 2.413 53.997 19.187 ;
     RECT  4.284 18.845 51.606 19.265 ;
     RECT  4.392 19.265 51.606 19.301 ;
     RECT  23.508 19.301 51.606 19.373 ;
     RECT  4.392 19.301 22.77 19.379 ;
     RECT  23.508 19.373 29.826 19.379 ;
     RECT  2.415 19.187 2.505 19.457 ;
     RECT  4.392 19.379 5.454 19.457 ;
     RECT  13.215 19.379 13.662 19.457 ;
     RECT  15.84 19.379 16.005 19.457 ;
     RECT  18.615 19.379 18.99 19.457 ;
     RECT  21.315 19.379 21.546 19.457 ;
     RECT  24.015 19.379 24.246 19.457 ;
     RECT  53.715 19.187 53.805 19.457 ;
     RECT  16.956 19.379 16.974 19.499 ;
     RECT  22.644 19.379 22.662 19.535 ;
     RECT  5.436 19.457 5.454 19.565 ;
     RECT  7.776 19.379 8.19 19.565 ;
     RECT  10.476 19.379 10.854 19.565 ;
     RECT  13.464 19.457 13.662 19.565 ;
     RECT  18.756 19.457 18.99 19.565 ;
     RECT  21.528 19.457 21.546 19.565 ;
     RECT  24.156 19.457 24.246 19.565 ;
     RECT  7.776 19.565 7.974 19.613 ;
     RECT  10.476 19.565 10.494 19.613 ;
     RECT  15.84 19.457 15.894 19.613 ;
     RECT  24.156 19.565 24.174 19.613 ;
     RECT  26.46 19.379 26.874 19.613 ;
     RECT  26.46 19.613 26.478 19.661 ;
     RECT  13.644 19.565 13.662 19.709 ;
     RECT  15.876 19.613 15.894 19.709 ;
     RECT  4.392 19.457 4.662 19.997 ;
     RECT  27.756 19.379 29.826 19.997 ;
     RECT  30.564 19.373 51.606 19.997 ;
     RECT  4.644 19.997 4.662 20.045 ;
     RECT  45.792 19.997 48.222 20.093 ;
     RECT  48.96 19.997 51.606 20.093 ;
     RECT  27.756 19.997 27.774 20.573 ;
     RECT  29.34 19.997 29.826 20.573 ;
     RECT  30.564 19.997 32.274 20.573 ;
     RECT  33.624 19.997 43.686 20.573 ;
     RECT  44.424 19.997 44.91 20.573 ;
     RECT  46.26 20.093 48.222 20.573 ;
     RECT  49.284 20.093 49.518 20.573 ;
     RECT  50.616 20.093 51.606 20.573 ;
     RECT  36.432 20.573 36.954 20.621 ;
     RECT  40.572 20.573 40.59 20.621 ;
     RECT  50.868 20.573 50.886 20.621 ;
     RECT  47.448 20.573 47.466 20.669 ;
     RECT  48.204 20.573 48.222 20.669 ;
     RECT  20.016 21.355 20.034 21.485 ;
    LAYER M4 ;
     RECT  0.156 10.8 2.408 10.824 ;
     RECT  2.408 2.148 2.512 19.452 ;
     RECT  2.512 2.418 2.704 19.182 ;
     RECT  4.021 18.192 4.453 18.216 ;
     RECT  4.453 18.192 4.501 18.408 ;
     RECT  4.381 19.968 4.501 19.992 ;
     RECT  4.501 18.192 4.633 19.992 ;
     RECT  4.501 1.728 4.837 1.752 ;
     RECT  4.633 18.192 4.849 20.04 ;
     RECT  4.837 1.728 5.021 1.8 ;
     RECT  5.021 1.728 5.108 1.896 ;
     RECT  4.957 17.088 5.108 17.112 ;
     RECT  4.849 18.096 5.108 20.04 ;
     RECT  5.108 1.728 5.219 20.04 ;
     RECT  5.219 1.728 5.404 19.56 ;
     RECT  5.404 16.656 5.465 19.56 ;
     RECT  5.404 1.728 5.573 2.28 ;
     RECT  4.633 0.192 5.669 0.216 ;
     RECT  5.465 16.656 5.789 19.368 ;
     RECT  5.669 0.192 5.893 0.264 ;
     RECT  5.789 18.192 6.041 19.368 ;
     RECT  5.404 14.256 6.469 14.712 ;
     RECT  5.789 16.656 6.509 17.208 ;
     RECT  5.893 0.192 6.565 1.224 ;
     RECT  5.573 2.256 6.565 2.28 ;
     RECT  6.565 0.192 6.725 2.28 ;
     RECT  6.509 16.656 6.757 17.16 ;
     RECT  6.725 0.576 6.761 2.28 ;
     RECT  6.469 14.256 6.865 15.192 ;
     RECT  6.865 14.16 7.045 15.192 ;
     RECT  6.757 16.464 7.045 17.16 ;
     RECT  7.045 14.16 7.117 17.16 ;
     RECT  7.117 13.92 7.513 17.16 ;
     RECT  6.041 18.48 7.513 19.368 ;
     RECT  7.513 13.92 7.724 19.368 ;
     RECT  6.761 0.576 7.765 0.696 ;
     RECT  6.761 1.728 7.808 2.28 ;
     RECT  7.093 6.288 7.808 6.312 ;
     RECT  7.724 13.92 7.808 19.608 ;
     RECT  7.808 1.728 7.996 19.608 ;
     RECT  7.996 1.728 8.104 19.56 ;
     RECT  7.765 0.192 8.165 0.696 ;
     RECT  8.104 13.68 8.201 19.56 ;
     RECT  8.104 6.288 8.237 6.312 ;
     RECT  8.165 0.576 8.293 0.696 ;
     RECT  8.104 1.728 8.293 1.752 ;
     RECT  8.293 0.576 8.957 1.752 ;
     RECT  8.957 0.576 9.157 0.6 ;
     RECT  9.157 0.192 9.497 0.6 ;
     RECT  8.957 1.68 9.539 1.752 ;
     RECT  9.539 1.728 10.165 1.752 ;
     RECT  8.201 13.68 10.46 19.368 ;
     RECT  10.165 1.728 10.465 1.8 ;
     RECT  10.465 1.728 10.508 2.04 ;
     RECT  9.877 3.936 10.508 3.96 ;
     RECT  10.46 13.68 10.508 19.608 ;
     RECT  10.508 1.728 10.547 19.608 ;
     RECT  10.547 1.728 10.804 19.56 ;
     RECT  9.497 0.192 10.837 0.264 ;
     RECT  10.804 13.632 10.909 19.56 ;
     RECT  10.837 0.192 11.516 0.6 ;
     RECT  10.804 1.728 11.516 2.28 ;
     RECT  11.516 0.192 11.603 2.28 ;
     RECT  10.804 6.288 11.729 6.312 ;
     RECT  11.603 1.728 11.891 2.28 ;
     RECT  10.909 13.632 11.941 19.368 ;
     RECT  11.941 13.584 12.157 19.368 ;
     RECT  11.603 0.192 12.161 0.6 ;
     RECT  12.157 13.152 12.572 19.368 ;
     RECT  12.161 0.576 12.701 0.6 ;
     RECT  11.891 1.728 12.901 1.752 ;
     RECT  12.901 1.728 13.208 1.848 ;
     RECT  13.057 3.408 13.208 3.432 ;
     RECT  12.421 5.712 13.208 5.736 ;
     RECT  12.572 13.008 13.208 19.368 ;
     RECT  13.208 1.728 13.237 19.452 ;
     RECT  13.237 1.728 13.504 19.608 ;
     RECT  13.504 13.056 13.621 19.608 ;
     RECT  13.621 13.056 13.708 19.704 ;
     RECT  13.237 0.192 13.765 0.216 ;
     RECT  13.504 1.728 13.765 1.752 ;
     RECT  13.708 13.056 13.789 19.368 ;
     RECT  13.765 0.192 13.817 1.752 ;
     RECT  13.504 5.712 14.609 5.736 ;
     RECT  13.789 13.632 14.867 19.368 ;
     RECT  13.817 0.576 15.281 1.752 ;
     RECT  15.281 0.576 15.493 1.8 ;
     RECT  15.493 0.528 15.577 1.8 ;
     RECT  14.867 13.68 15.788 19.368 ;
     RECT  15.788 13.68 15.865 19.608 ;
     RECT  15.577 0.528 15.869 2.28 ;
     RECT  15.869 1.728 15.908 2.28 ;
     RECT  13.504 3.408 15.908 3.432 ;
     RECT  15.157 6.576 15.908 6.6 ;
     RECT  15.865 13.68 15.908 19.704 ;
     RECT  15.908 1.728 16.067 19.704 ;
     RECT  16.001 0.192 16.085 0.216 ;
     RECT  16.067 1.728 16.204 19.656 ;
     RECT  16.204 13.104 16.499 19.656 ;
     RECT  16.204 1.728 16.732 3.24 ;
     RECT  16.499 13.104 16.787 19.368 ;
     RECT  16.732 1.728 17.075 2.28 ;
     RECT  17.075 1.728 17.18 1.848 ;
     RECT  16.787 13.632 17.237 19.368 ;
     RECT  17.18 1.68 17.267 1.848 ;
     RECT  17.693 0.576 17.777 0.6 ;
     RECT  17.267 1.728 18.229 1.848 ;
     RECT  17.237 13.68 18.469 19.368 ;
     RECT  18.229 1.152 18.524 1.848 ;
     RECT  18.524 1.152 18.608 2.04 ;
     RECT  18.469 13.68 18.608 19.608 ;
     RECT  18.608 1.152 18.611 19.608 ;
     RECT  18.611 1.152 18.753 19.56 ;
     RECT  18.753 0.192 18.904 19.56 ;
     RECT  18.904 13.68 19.036 19.56 ;
     RECT  18.904 0.192 19.757 1.752 ;
     RECT  19.757 0.192 19.837 0.6 ;
     RECT  19.957 21.36 20.005 21.384 ;
     RECT  20.005 21.36 20.045 21.48 ;
     RECT  20.045 21.456 20.089 21.48 ;
     RECT  19.757 1.728 20.293 1.752 ;
     RECT  20.293 1.728 20.437 1.848 ;
     RECT  19.837 0.576 20.905 0.6 ;
     RECT  20.905 0.48 21.011 0.6 ;
     RECT  19.036 13.68 21.109 19.368 ;
     RECT  21.109 13.68 21.121 19.608 ;
     RECT  20.437 1.728 21.308 2.28 ;
     RECT  21.109 6.24 21.308 6.264 ;
     RECT  21.121 13.584 21.308 19.608 ;
     RECT  21.308 1.728 21.395 19.608 ;
     RECT  21.395 1.728 21.58 19.56 ;
     RECT  21.58 1.728 21.604 19.368 ;
     RECT  21.011 0.576 21.685 0.6 ;
     RECT  21.604 1.728 21.685 1.752 ;
     RECT  21.685 0.576 22.165 1.752 ;
     RECT  22.165 0.192 22.601 1.752 ;
     RECT  22.601 0.576 23.357 1.752 ;
     RECT  22.741 3.408 23.557 3.432 ;
     RECT  21.604 13.584 23.569 19.368 ;
     RECT  22.693 5.712 23.749 5.736 ;
     RECT  23.357 0.576 23.824 1.176 ;
     RECT  23.557 2.832 24.008 3.432 ;
     RECT  23.749 5.712 24.008 6.312 ;
     RECT  23.569 13.104 24.008 19.368 ;
     RECT  23.824 0.528 24.085 1.176 ;
     RECT  24.008 2.148 24.085 19.452 ;
     RECT  24.085 2.148 24.112 19.608 ;
     RECT  24.112 2.256 24.185 19.608 ;
     RECT  24.185 2.256 24.275 19.56 ;
     RECT  24.275 2.256 24.304 19.368 ;
     RECT  24.085 0.192 25.013 1.176 ;
     RECT  24.304 2.256 25.253 2.28 ;
     RECT  24.304 13.584 25.333 19.368 ;
     RECT  25.013 0.192 25.481 0.216 ;
     RECT  25.333 13.296 25.585 19.368 ;
     RECT  25.253 1.728 25.667 2.28 ;
     RECT  25.585 12.528 26.449 19.368 ;
     RECT  26.444 0.528 26.665 0.552 ;
     RECT  25.667 1.728 26.708 1.752 ;
     RECT  25.813 6.288 26.708 6.312 ;
     RECT  26.449 12.528 26.708 19.656 ;
     RECT  26.708 1.728 27.004 19.656 ;
     RECT  27.004 13.104 27.209 19.656 ;
     RECT  27.209 13.296 27.317 19.656 ;
     RECT  26.665 0.048 27.349 0.552 ;
     RECT  27.317 13.488 27.635 19.656 ;
     RECT  27.349 0.048 27.677 0.6 ;
     RECT  27.635 13.68 27.745 19.656 ;
     RECT  27.677 0.048 28.019 0.264 ;
     RECT  27.004 1.728 28.105 1.8 ;
     RECT  27.745 13.68 28.307 20.568 ;
     RECT  28.019 0.192 28.333 0.264 ;
     RECT  28.333 0.24 28.451 0.264 ;
     RECT  28.105 1.728 28.748 2.28 ;
     RECT  28.307 13.68 28.753 19.992 ;
     RECT  28.748 0.528 28.979 2.28 ;
     RECT  28.753 13.104 29.269 19.992 ;
     RECT  28.979 0.528 29.315 0.6 ;
     RECT  28.979 1.632 29.408 2.28 ;
     RECT  29.269 13.104 29.408 20.568 ;
     RECT  29.315 0.528 29.507 0.552 ;
     RECT  29.408 1.632 29.704 20.568 ;
     RECT  29.797 0.192 30.589 0.216 ;
     RECT  29.704 1.632 30.589 1.752 ;
     RECT  29.704 13.68 30.629 20.568 ;
     RECT  30.589 0.192 30.665 1.752 ;
     RECT  30.665 0.192 30.707 1.704 ;
     RECT  30.629 13.68 30.899 18.84 ;
     RECT  30.707 1.68 31.841 1.704 ;
     RECT  30.899 13.68 31.861 18.792 ;
     RECT  30.629 19.968 31.861 20.568 ;
     RECT  30.707 0.192 31.921 0.6 ;
     RECT  31.841 1.68 31.921 1.752 ;
     RECT  31.921 0.192 31.957 1.752 ;
     RECT  31.885 2.832 31.957 2.856 ;
     RECT  31.957 0.192 32.108 2.856 ;
     RECT  31.993 10.896 32.108 10.92 ;
     RECT  31.861 13.68 32.108 20.568 ;
     RECT  32.108 0.192 32.285 20.568 ;
     RECT  32.285 0.192 32.404 19.992 ;
     RECT  32.404 0.192 32.435 1.992 ;
     RECT  32.404 13.68 32.963 19.992 ;
     RECT  32.435 0.192 33.113 1.176 ;
     RECT  32.963 13.68 33.443 18.84 ;
     RECT  32.963 19.968 33.589 19.992 ;
     RECT  33.548 2.256 34.364 2.28 ;
     RECT  33.443 13.68 34.412 18.792 ;
     RECT  33.589 19.968 34.412 20.568 ;
     RECT  34.364 2.16 34.808 2.28 ;
     RECT  34.412 13.68 34.808 20.568 ;
     RECT  34.808 2.148 35.104 20.568 ;
     RECT  33.113 0.192 35.485 1.128 ;
     RECT  35.104 13.68 35.884 20.568 ;
     RECT  35.485 0.192 36.245 1.752 ;
     RECT  35.884 19.968 36.245 20.568 ;
     RECT  36.245 20.544 36.421 20.568 ;
     RECT  36.421 20.544 37.043 20.616 ;
     RECT  35.884 13.68 37.148 18.792 ;
     RECT  36.245 0.576 37.321 1.752 ;
     RECT  37.148 13.68 37.321 19.416 ;
     RECT  37.043 20.544 37.321 20.568 ;
     RECT  37.321 0.528 37.508 1.752 ;
     RECT  36.457 2.832 37.508 2.856 ;
     RECT  37.321 13.68 37.508 20.568 ;
     RECT  37.508 0.528 37.717 20.568 ;
     RECT  37.717 0.192 37.804 20.568 ;
     RECT  37.804 13.68 37.865 20.568 ;
     RECT  37.804 0.192 37.945 1.752 ;
     RECT  37.804 2.88 38.243 2.904 ;
     RECT  37.945 0.192 38.435 1.704 ;
     RECT  38.435 1.68 39.107 1.704 ;
     RECT  39.02 3.408 39.107 3.432 ;
     RECT  37.865 13.68 39.157 18.84 ;
     RECT  39.157 1.728 39.212 1.752 ;
     RECT  39.212 1.728 39.301 2.28 ;
     RECT  39.157 13.68 39.517 18.888 ;
     RECT  37.865 19.968 39.517 20.568 ;
     RECT  38.435 0.192 40.163 0.552 ;
     RECT  39.301 1.728 40.208 2.904 ;
     RECT  39.517 13.68 40.208 20.568 ;
     RECT  40.163 0.24 40.307 0.552 ;
     RECT  40.208 1.728 40.307 20.568 ;
     RECT  40.307 1.728 40.504 19.56 ;
     RECT  40.307 20.544 40.561 20.568 ;
     RECT  40.504 1.728 40.604 1.752 ;
     RECT  40.504 13.68 40.643 19.56 ;
     RECT  40.561 20.544 41.171 20.616 ;
     RECT  40.604 1.104 41.249 1.752 ;
     RECT  41.249 1.104 41.507 1.704 ;
     RECT  40.643 13.68 41.507 19.416 ;
     RECT  41.171 20.544 41.612 20.568 ;
     RECT  41.605 0.576 42.264 0.6 ;
     RECT  42.264 0.528 42.677 0.6 ;
     RECT  42.677 0.192 42.899 0.6 ;
     RECT  41.507 1.68 42.908 1.704 ;
     RECT  42.757 6 42.908 6.024 ;
     RECT  41.507 13.68 42.908 18.84 ;
     RECT  41.612 19.968 42.908 20.568 ;
     RECT  42.908 1.68 43.091 20.568 ;
     RECT  43.091 1.68 43.204 19.416 ;
     RECT  43.204 13.68 43.427 19.416 ;
     RECT  42.899 0.192 43.445 0.216 ;
     RECT  43.204 1.68 43.477 2.28 ;
     RECT  43.477 1.632 43.955 2.28 ;
     RECT  43.955 1.632 44.204 1.752 ;
     RECT  43.427 13.68 44.273 15.048 ;
     RECT  43.427 16.032 44.291 19.416 ;
     RECT  43.091 20.544 44.341 20.568 ;
     RECT  44.341 19.968 44.963 20.568 ;
     RECT  44.291 16.032 45.277 18.792 ;
     RECT  44.963 19.968 45.277 20.088 ;
     RECT  44.204 0.528 45.608 1.752 ;
     RECT  44.953 3.264 45.608 3.288 ;
     RECT  44.273 14.112 45.608 15.048 ;
     RECT  45.277 16.032 45.608 20.088 ;
     RECT  45.608 0.528 45.904 20.088 ;
     RECT  45.904 0.528 46.001 3.24 ;
     RECT  46.001 2.208 46.019 3.24 ;
     RECT  46.001 0.528 46.037 1.176 ;
     RECT  45.904 16.032 46.067 20.088 ;
     RECT  46.037 0.528 46.097 1.128 ;
     RECT  46.067 16.032 46.109 18.264 ;
     RECT  46.109 18.24 46.163 18.264 ;
     RECT  46.067 19.392 46.249 20.088 ;
     RECT  46.097 0.192 46.499 1.128 ;
     RECT  45.904 15.024 46.649 15.048 ;
     RECT  46.019 2.208 46.835 2.28 ;
     RECT  46.249 19.392 47.027 20.568 ;
     RECT  46.835 2.256 47.257 2.28 ;
     RECT  46.109 16.032 47.297 17.16 ;
     RECT  47.027 19.968 47.437 20.568 ;
     RECT  46.499 0.192 47.621 0.6 ;
     RECT  47.621 0.528 47.869 0.6 ;
     RECT  47.869 0.528 47.905 1.128 ;
     RECT  47.257 2.256 47.905 2.904 ;
     RECT  47.905 0.528 48.308 2.904 ;
     RECT  47.297 16.032 48.308 16.056 ;
     RECT  47.297 17.136 48.308 17.16 ;
     RECT  47.437 19.968 48.308 20.664 ;
     RECT  48.308 0.528 48.563 20.664 ;
     RECT  48.563 2.256 48.604 20.664 ;
     RECT  48.563 0.528 48.755 1.128 ;
     RECT  48.604 19.392 48.755 20.664 ;
     RECT  48.755 0.528 48.833 0.6 ;
     RECT  48.755 19.968 48.899 20.664 ;
     RECT  48.604 17.136 48.953 17.16 ;
     RECT  48.833 0.192 49.105 0.6 ;
     RECT  48.604 2.256 49.235 2.28 ;
     RECT  48.899 19.968 49.619 20.568 ;
     RECT  49.777 1.68 49.954 1.704 ;
     RECT  49.954 1.632 50.099 1.704 ;
     RECT  49.105 0.192 50.137 0.264 ;
     RECT  50.137 0.192 50.417 0.552 ;
     RECT  49.619 19.968 50.581 20.088 ;
     RECT  50.741 1.728 50.749 1.752 ;
     RECT  50.749 1.728 50.825 1.992 ;
     RECT  50.581 19.968 50.857 20.568 ;
     RECT  50.825 1.968 50.876 1.992 ;
     RECT  50.857 19.968 50.963 20.616 ;
     RECT  50.876 1.968 51.008 2.04 ;
     RECT  50.173 18.768 51.008 18.792 ;
     RECT  50.963 19.968 51.008 20.568 ;
     RECT  50.417 0.192 51.185 0.6 ;
     RECT  51.008 1.968 51.196 20.568 ;
     RECT  51.196 1.968 51.299 19.56 ;
     RECT  51.299 2.16 51.304 19.56 ;
     RECT  51.185 0.192 51.517 0.216 ;
     RECT  51.304 18.816 51.581 19.56 ;
     RECT  51.196 20.544 51.617 20.568 ;
     RECT  51.581 18.816 51.869 18.84 ;
     RECT  51.304 2.16 51.905 2.184 ;
     RECT  53.708 2.148 53.812 19.452 ;
     RECT  53.812 2.418 54.004 19.182 ;
    LAYER M5 ;
     RECT  27.984 0.037 28.008 0.144 ;
     RECT  4.512 0.144 51.672 0.611 ;
     RECT  4.512 0.611 42.552 1.139 ;
     RECT  29.664 1.139 34.488 1.187 ;
     RECT  4.512 1.139 28.632 1.715 ;
     RECT  29.664 1.187 32.424 1.715 ;
     RECT  35.808 1.139 42.552 1.715 ;
     RECT  43.536 0.611 51.672 1.715 ;
     RECT  4.512 1.715 9 1.763 ;
     RECT  9.984 1.715 28.632 1.763 ;
     RECT  29.664 1.715 30.504 1.763 ;
     RECT  31.872 1.715 32.424 1.763 ;
     RECT  35.808 1.715 38.232 1.763 ;
     RECT  39.264 1.715 41.16 1.763 ;
     RECT  43.536 1.715 49.224 1.763 ;
     RECT  50.784 1.715 51.672 1.763 ;
     RECT  4.848 1.763 8.112 1.811 ;
     RECT  10.176 1.763 13.992 1.811 ;
     RECT  15.168 1.763 18.912 1.811 ;
     RECT  22.704 1.763 28.632 1.811 ;
     RECT  15.168 1.811 17.592 1.859 ;
     RECT  20.304 1.763 21.612 1.859 ;
     RECT  5.04 1.811 8.112 1.907 ;
     RECT  31.968 1.763 32.424 2.003 ;
     RECT  18.576 1.811 18.912 2.051 ;
     RECT  50.928 1.763 51.672 2.051 ;
     RECT  28.608 1.811 28.632 2.137 ;
     RECT  29.664 1.763 29.712 2.137 ;
     RECT  33.6 1.187 34.488 2.137 ;
     RECT  43.536 1.763 43.944 2.137 ;
     RECT  2.4 2.137 2.52 2.151 ;
     RECT  53.7 2.137 53.82 2.151 ;
     RECT  51 2.051 51.672 2.195 ;
     RECT  5.1 1.907 8.112 2.291 ;
     RECT  15.168 1.859 17.064 2.291 ;
     RECT  20.496 1.859 21.612 2.291 ;
     RECT  22.704 1.811 27.012 2.291 ;
     RECT  28.608 2.137 29.712 2.291 ;
     RECT  33.6 2.137 35.112 2.291 ;
     RECT  42.9 2.137 43.944 2.291 ;
     RECT  45.12 1.763 49.224 2.291 ;
     RECT  31.968 2.003 32.412 2.867 ;
     RECT  36.528 1.763 38.232 2.867 ;
     RECT  37.5 2.867 38.232 2.915 ;
     RECT  47.328 2.291 48.612 2.915 ;
     RECT  45.12 2.291 46.008 3.299 ;
     RECT  39.264 1.763 40.512 3.397 ;
     RECT  10.5 1.811 13.992 3.925 ;
     RECT  9.888 3.925 13.992 5.747 ;
     RECT  22.704 2.291 24.312 5.747 ;
     RECT  42.9 2.291 43.212 5.989 ;
     RECT  21.3 2.291 21.612 6.229 ;
     RECT  7.104 2.291 8.112 6.323 ;
     RECT  9.888 5.747 11.88 6.323 ;
     RECT  25.824 2.291 27.012 6.323 ;
     RECT  15.168 2.291 16.68 6.611 ;
     RECT  26.7 6.323 27.012 12.517 ;
     RECT  11.856 6.323 11.88 12.997 ;
     RECT  13.2 5.747 13.512 12.997 ;
     RECT  11.856 12.997 13.512 13.045 ;
     RECT  15.216 6.611 16.68 13.093 ;
     RECT  26.496 12.517 27.012 13.477 ;
     RECT  26.496 13.477 27.624 13.573 ;
     RECT  15.216 13.093 16.776 13.621 ;
     RECT  21.12 6.229 21.612 13.621 ;
     RECT  23.568 5.747 24.312 13.621 ;
     RECT  26.208 13.573 27.624 13.621 ;
     RECT  9.888 6.323 10.812 13.669 ;
     RECT  11.856 13.045 13.752 13.669 ;
     RECT  21.12 13.621 24.312 13.669 ;
     RECT  25.968 13.621 27.624 13.669 ;
     RECT  32.1 2.867 32.412 13.717 ;
     RECT  39.072 3.397 40.512 13.717 ;
     RECT  7.8 6.323 8.112 13.813 ;
     RECT  14.832 13.621 16.776 13.861 ;
     RECT  9.888 13.669 13.752 13.957 ;
     RECT  14.832 13.861 17.16 13.957 ;
     RECT  18.6 2.051 18.912 14.101 ;
     RECT  18.144 14.101 18.912 14.341 ;
     RECT  29.4 2.291 29.712 14.341 ;
     RECT  7.8 13.813 8.568 14.485 ;
     RECT  21.12 13.669 27.624 14.533 ;
     RECT  29.232 14.341 29.712 14.581 ;
     RECT  18.144 14.341 19.224 14.675 ;
     RECT  18.144 14.675 19.128 14.771 ;
     RECT  9.888 13.957 17.16 14.773 ;
     RECT  18.144 14.771 19.032 14.773 ;
     RECT  29.136 14.581 29.712 14.821 ;
     RECT  31.968 13.717 32.412 15.157 ;
     RECT  31.056 15.157 32.412 15.299 ;
     RECT  9.888 14.773 19.032 15.349 ;
     RECT  20.832 14.533 27.624 15.397 ;
     RECT  7.8 14.485 8.664 15.973 ;
     RECT  42.768 5.989 43.212 15.973 ;
     RECT  28.656 14.821 29.712 16.165 ;
     RECT  9.648 15.349 19.032 16.501 ;
     RECT  20.448 15.397 27.624 16.501 ;
     RECT  28.656 16.165 30.072 16.501 ;
     RECT  7.536 15.973 8.664 16.549 ;
     RECT  31.968 15.299 32.412 16.549 ;
     RECT  38.832 13.717 40.512 16.549 ;
     RECT  31.968 16.549 32.568 16.693 ;
     RECT  9.648 16.501 30.072 16.739 ;
     RECT  31.44 16.693 32.568 16.835 ;
     RECT  7.44 16.549 8.664 16.981 ;
     RECT  9.648 16.739 28.008 16.981 ;
     RECT  34.416 2.291 35.112 17.077 ;
     RECT  36.336 16.117 36.36 17.077 ;
     RECT  7.44 16.981 28.008 17.123 ;
     RECT  7.44 17.123 8.112 17.171 ;
     RECT  29.04 16.739 30.072 17.653 ;
     RECT  11.808 17.123 28.008 17.699 ;
     RECT  13.2 17.699 28.008 17.747 ;
     RECT  23.04 17.747 28.008 17.797 ;
     RECT  29.04 17.653 30.168 17.797 ;
     RECT  9.888 17.123 10.812 18.181 ;
     RECT  11.808 17.699 12.168 18.181 ;
     RECT  23.04 17.797 30.168 18.229 ;
     RECT  31.968 16.835 32.568 18.229 ;
     RECT  45.6 3.299 46.008 18.229 ;
     RECT  34.416 17.077 36.36 18.419 ;
     RECT  38.832 16.549 40.632 18.563 ;
     RECT  13.2 17.747 21.768 18.709 ;
     RECT  23.04 18.229 30.36 18.709 ;
     RECT  45.6 18.229 46.152 18.757 ;
     RECT  51 2.195 51.312 18.757 ;
     RECT  5.1 2.291 5.412 18.805 ;
     RECT  7.68 17.171 8.112 18.805 ;
     RECT  9.888 18.181 12.168 18.805 ;
     RECT  13.2 18.709 30.36 18.805 ;
     RECT  31.344 18.229 32.568 18.805 ;
     RECT  38.928 18.563 40.632 18.805 ;
     RECT  42.768 15.973 43.416 18.805 ;
     RECT  50.256 18.757 51.312 18.805 ;
     RECT  4.656 18.805 33.432 19.333 ;
     RECT  34.8 18.419 36.36 19.381 ;
     RECT  37.5 2.915 37.812 19.381 ;
     RECT  38.928 18.805 41.352 19.381 ;
     RECT  42.72 18.805 44.088 19.381 ;
     RECT  45.12 18.757 46.152 19.381 ;
     RECT  48.3 2.915 48.612 19.381 ;
     RECT  2.4 2.151 2.712 19.449 ;
     RECT  53.7 2.151 54.012 19.449 ;
     RECT  2.4 19.449 2.52 19.463 ;
     RECT  53.7 19.449 53.82 19.463 ;
     RECT  4.512 19.333 33.432 19.957 ;
     RECT  34.464 19.381 37.812 19.957 ;
     RECT  38.928 19.381 41.496 19.957 ;
     RECT  42.72 19.381 47.016 19.957 ;
     RECT  48.3 19.381 48.744 19.957 ;
     RECT  50.256 18.805 51.672 19.957 ;
     RECT  4.512 19.957 51.672 21.456 ;
     RECT  20.016 21.456 20.04 21.491 ;
  END
END hbfd_rly_136_NS_fc_f3
END LIBRARY
